VERSION 5.8 ;
BUSBITCHARS "[]" ;
DIVIDERCHAR "/" ;
UNITS
    DATABASE MICRONS 1000 ;
END UNITS

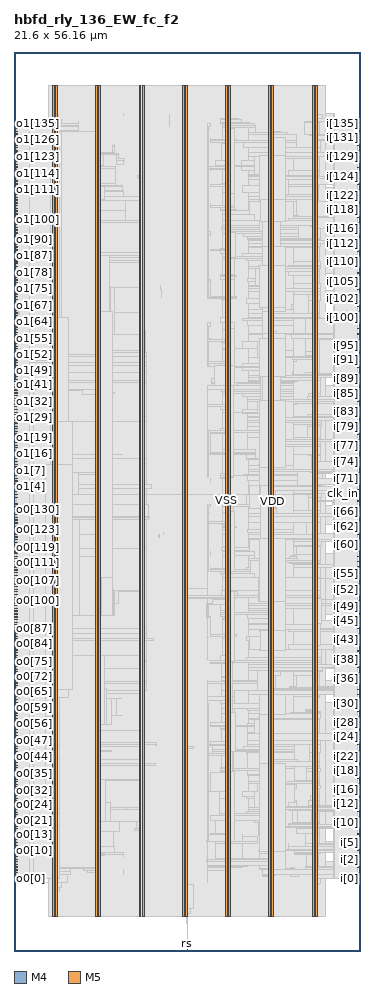
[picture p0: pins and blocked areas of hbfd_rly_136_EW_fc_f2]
MACRO hbfd_rly_136_EW_fc_f2
  FOREIGN hbfd_rly_136_EW_fc_f2 0 0 ;
  CLASS BLOCK ;
  SIZE 21.6 BY 56.16 ;
  PIN clk_in
    DIRECTION INPUT ;
    USE SIGNAL ;
    PORT
      LAYER M4 ;
        RECT  21.408 28.08 21.6 28.104 ;
    END
  END clk_in
  PIN clk_out0
    DIRECTION OUTPUT ;
    USE SIGNAL ;
    PORT
      LAYER M4 ;
        RECT  0 16.224 0.192 16.248 ;
    END
  END clk_out0
  PIN clk_out1
    DIRECTION OUTPUT ;
    USE SIGNAL ;
    PORT
      LAYER M4 ;
        RECT  0 39.984 0.192 40.008 ;
    END
  END clk_out1
  PIN i[0]
    DIRECTION INPUT ;
    USE SIGNAL ;
    PORT
      LAYER M4 ;
        RECT  21.408 4.512 21.6 4.536 ;
    END
  END i[0]
  PIN i[100]
    DIRECTION INPUT ;
    USE SIGNAL ;
    PORT
      LAYER M4 ;
        RECT  21.408 39.504 21.6 39.528 ;
    END
  END i[100]
  PIN i[101]
    DIRECTION INPUT ;
    USE SIGNAL ;
    PORT
      LAYER M4 ;
        RECT  21.408 39.888 21.6 39.912 ;
    END
  END i[101]
  PIN i[102]
    DIRECTION INPUT ;
    USE SIGNAL ;
    PORT
      LAYER M4 ;
        RECT  21.408 40.224 21.6 40.248 ;
    END
  END i[102]
  PIN i[103]
    DIRECTION INPUT ;
    USE SIGNAL ;
    PORT
      LAYER M4 ;
        RECT  21.408 40.56 21.6 40.584 ;
    END
  END i[103]
  PIN i[104]
    DIRECTION INPUT ;
    USE SIGNAL ;
    PORT
      LAYER M4 ;
        RECT  21.408 40.896 21.6 40.92 ;
    END
  END i[104]
  PIN i[105]
    DIRECTION INPUT ;
    USE SIGNAL ;
    PORT
      LAYER M4 ;
        RECT  21.408 41.28 21.6 41.304 ;
    END
  END i[105]
  PIN i[106]
    DIRECTION INPUT ;
    USE SIGNAL ;
    PORT
      LAYER M4 ;
        RECT  21.408 41.616 21.6 41.64 ;
    END
  END i[106]
  PIN i[107]
    DIRECTION INPUT ;
    USE SIGNAL ;
    PORT
      LAYER M4 ;
        RECT  21.408 41.952 21.6 41.976 ;
    END
  END i[107]
  PIN i[108]
    DIRECTION INPUT ;
    USE SIGNAL ;
    PORT
      LAYER M4 ;
        RECT  21.408 42.288 21.6 42.312 ;
    END
  END i[108]
  PIN i[109]
    DIRECTION INPUT ;
    USE SIGNAL ;
    PORT
      LAYER M4 ;
        RECT  21.408 42.624 21.6 42.648 ;
    END
  END i[109]
  PIN i[10]
    DIRECTION INPUT ;
    USE SIGNAL ;
    PORT
      LAYER M4 ;
        RECT  21.408 8.016 21.6 8.04 ;
    END
  END i[10]
  PIN i[110]
    DIRECTION INPUT ;
    USE SIGNAL ;
    PORT
      LAYER M4 ;
        RECT  21.408 43.008 21.6 43.032 ;
    END
  END i[110]
  PIN i[111]
    DIRECTION INPUT ;
    USE SIGNAL ;
    PORT
      LAYER M4 ;
        RECT  21.408 43.344 21.6 43.368 ;
    END
  END i[111]
  PIN i[112]
    DIRECTION INPUT ;
    USE SIGNAL ;
    PORT
      LAYER M4 ;
        RECT  21.408 43.68 21.6 43.704 ;
    END
  END i[112]
  PIN i[113]
    DIRECTION INPUT ;
    USE SIGNAL ;
    PORT
      LAYER M4 ;
        RECT  21.408 44.016 21.6 44.04 ;
    END
  END i[113]
  PIN i[114]
    DIRECTION INPUT ;
    USE SIGNAL ;
    PORT
      LAYER M4 ;
        RECT  21.408 44.4 21.6 44.424 ;
    END
  END i[114]
  PIN i[115]
    DIRECTION INPUT ;
    USE SIGNAL ;
    PORT
      LAYER M4 ;
        RECT  21.408 44.736 21.6 44.76 ;
    END
  END i[115]
  PIN i[116]
    DIRECTION INPUT ;
    USE SIGNAL ;
    PORT
      LAYER M4 ;
        RECT  21.408 45.072 21.6 45.096 ;
    END
  END i[116]
  PIN i[117]
    DIRECTION INPUT ;
    USE SIGNAL ;
    PORT
      LAYER M4 ;
        RECT  21.408 45.408 21.6 45.432 ;
    END
  END i[117]
  PIN i[118]
    DIRECTION INPUT ;
    USE SIGNAL ;
    PORT
      LAYER M4 ;
        RECT  21.408 45.744 21.6 45.768 ;
    END
  END i[118]
  PIN i[119]
    DIRECTION INPUT ;
    USE SIGNAL ;
    PORT
      LAYER M4 ;
        RECT  21.408 46.128 21.6 46.152 ;
    END
  END i[119]
  PIN i[11]
    DIRECTION INPUT ;
    USE SIGNAL ;
    PORT
      LAYER M4 ;
        RECT  21.408 8.352 21.6 8.376 ;
    END
  END i[11]
  PIN i[120]
    DIRECTION INPUT ;
    USE SIGNAL ;
    PORT
      LAYER M4 ;
        RECT  21.408 46.464 21.6 46.488 ;
    END
  END i[120]
  PIN i[121]
    DIRECTION INPUT ;
    USE SIGNAL ;
    PORT
      LAYER M4 ;
        RECT  21.408 46.8 21.6 46.824 ;
    END
  END i[121]
  PIN i[122]
    DIRECTION INPUT ;
    USE SIGNAL ;
    PORT
      LAYER M4 ;
        RECT  21.408 47.136 21.6 47.16 ;
    END
  END i[122]
  PIN i[123]
    DIRECTION INPUT ;
    USE SIGNAL ;
    PORT
      LAYER M4 ;
        RECT  21.408 47.472 21.6 47.496 ;
    END
  END i[123]
  PIN i[124]
    DIRECTION INPUT ;
    USE SIGNAL ;
    PORT
      LAYER M4 ;
        RECT  21.408 47.856 21.6 47.88 ;
    END
  END i[124]
  PIN i[125]
    DIRECTION INPUT ;
    USE SIGNAL ;
    PORT
      LAYER M4 ;
        RECT  21.408 48.192 21.6 48.216 ;
    END
  END i[125]
  PIN i[126]
    DIRECTION INPUT ;
    USE SIGNAL ;
    PORT
      LAYER M4 ;
        RECT  21.408 48.528 21.6 48.552 ;
    END
  END i[126]
  PIN i[127]
    DIRECTION INPUT ;
    USE SIGNAL ;
    PORT
      LAYER M4 ;
        RECT  21.408 48.864 21.6 48.888 ;
    END
  END i[127]
  PIN i[128]
    DIRECTION INPUT ;
    USE SIGNAL ;
    PORT
      LAYER M4 ;
        RECT  21.408 49.248 21.6 49.272 ;
    END
  END i[128]
  PIN i[129]
    DIRECTION INPUT ;
    USE SIGNAL ;
    PORT
      LAYER M4 ;
        RECT  21.408 49.584 21.6 49.608 ;
    END
  END i[129]
  PIN i[12]
    DIRECTION INPUT ;
    USE SIGNAL ;
    PORT
      LAYER M4 ;
        RECT  21.408 8.688 21.6 8.712 ;
    END
  END i[12]
  PIN i[130]
    DIRECTION INPUT ;
    USE SIGNAL ;
    PORT
      LAYER M4 ;
        RECT  21.408 49.92 21.6 49.944 ;
    END
  END i[130]
  PIN i[131]
    DIRECTION INPUT ;
    USE SIGNAL ;
    PORT
      LAYER M4 ;
        RECT  21.408 50.256 21.6 50.28 ;
    END
  END i[131]
  PIN i[132]
    DIRECTION INPUT ;
    USE SIGNAL ;
    PORT
      LAYER M4 ;
        RECT  21.408 50.592 21.6 50.616 ;
    END
  END i[132]
  PIN i[133]
    DIRECTION INPUT ;
    USE SIGNAL ;
    PORT
      LAYER M4 ;
        RECT  21.408 50.976 21.6 51 ;
    END
  END i[133]
  PIN i[134]
    DIRECTION INPUT ;
    USE SIGNAL ;
    PORT
      LAYER M4 ;
        RECT  21.408 51.312 21.6 51.336 ;
    END
  END i[134]
  PIN i[135]
    DIRECTION INPUT ;
    USE SIGNAL ;
    PORT
      LAYER M4 ;
        RECT  21.408 51.648 21.6 51.672 ;
    END
  END i[135]
  PIN i[13]
    DIRECTION INPUT ;
    USE SIGNAL ;
    PORT
      LAYER M4 ;
        RECT  21.408 9.024 21.6 9.048 ;
    END
  END i[13]
  PIN i[14]
    DIRECTION INPUT ;
    USE SIGNAL ;
    PORT
      LAYER M4 ;
        RECT  21.408 9.36 21.6 9.384 ;
    END
  END i[14]
  PIN i[15]
    DIRECTION INPUT ;
    USE SIGNAL ;
    PORT
      LAYER M4 ;
        RECT  21.408 9.744 21.6 9.768 ;
    END
  END i[15]
  PIN i[16]
    DIRECTION INPUT ;
    USE SIGNAL ;
    PORT
      LAYER M4 ;
        RECT  21.408 10.08 21.6 10.104 ;
    END
  END i[16]
  PIN i[17]
    DIRECTION INPUT ;
    USE SIGNAL ;
    PORT
      LAYER M4 ;
        RECT  21.408 10.416 21.6 10.44 ;
    END
  END i[17]
  PIN i[18]
    DIRECTION INPUT ;
    USE SIGNAL ;
    PORT
      LAYER M4 ;
        RECT  21.408 10.752 21.6 10.776 ;
    END
  END i[18]
  PIN i[19]
    DIRECTION INPUT ;
    USE SIGNAL ;
    PORT
      LAYER M4 ;
        RECT  21.408 11.136 21.6 11.16 ;
    END
  END i[19]
  PIN i[1]
    DIRECTION INPUT ;
    USE SIGNAL ;
    PORT
      LAYER M4 ;
        RECT  21.408 4.896 21.6 4.92 ;
    END
  END i[1]
  PIN i[20]
    DIRECTION INPUT ;
    USE SIGNAL ;
    PORT
      LAYER M4 ;
        RECT  21.408 11.472 21.6 11.496 ;
    END
  END i[20]
  PIN i[21]
    DIRECTION INPUT ;
    USE SIGNAL ;
    PORT
      LAYER M4 ;
        RECT  21.408 11.808 21.6 11.832 ;
    END
  END i[21]
  PIN i[22]
    DIRECTION INPUT ;
    USE SIGNAL ;
    PORT
      LAYER M4 ;
        RECT  21.408 12.144 21.6 12.168 ;
    END
  END i[22]
  PIN i[23]
    DIRECTION INPUT ;
    USE SIGNAL ;
    PORT
      LAYER M4 ;
        RECT  21.408 12.48 21.6 12.504 ;
    END
  END i[23]
  PIN i[24]
    DIRECTION INPUT ;
    USE SIGNAL ;
    PORT
      LAYER M4 ;
        RECT  21.408 12.864 21.6 12.888 ;
    END
  END i[24]
  PIN i[25]
    DIRECTION INPUT ;
    USE SIGNAL ;
    PORT
      LAYER M4 ;
        RECT  21.408 13.2 21.6 13.224 ;
    END
  END i[25]
  PIN i[26]
    DIRECTION INPUT ;
    USE SIGNAL ;
    PORT
      LAYER M4 ;
        RECT  21.408 13.536 21.6 13.56 ;
    END
  END i[26]
  PIN i[27]
    DIRECTION INPUT ;
    USE SIGNAL ;
    PORT
      LAYER M4 ;
        RECT  21.408 13.872 21.6 13.896 ;
    END
  END i[27]
  PIN i[28]
    DIRECTION INPUT ;
    USE SIGNAL ;
    PORT
      LAYER M4 ;
        RECT  21.408 14.256 21.6 14.28 ;
    END
  END i[28]
  PIN i[29]
    DIRECTION INPUT ;
    USE SIGNAL ;
    PORT
      LAYER M4 ;
        RECT  21.408 14.592 21.6 14.616 ;
    END
  END i[29]
  PIN i[2]
    DIRECTION INPUT ;
    USE SIGNAL ;
    PORT
      LAYER M4 ;
        RECT  21.408 5.232 21.6 5.256 ;
    END
  END i[2]
  PIN i[30]
    DIRECTION INPUT ;
    USE SIGNAL ;
    PORT
      LAYER M4 ;
        RECT  21.408 14.928 21.6 14.952 ;
    END
  END i[30]
  PIN i[31]
    DIRECTION INPUT ;
    USE SIGNAL ;
    PORT
      LAYER M4 ;
        RECT  21.408 15.264 21.6 15.288 ;
    END
  END i[31]
  PIN i[32]
    DIRECTION INPUT ;
    USE SIGNAL ;
    PORT
      LAYER M4 ;
        RECT  21.408 15.6 21.6 15.624 ;
    END
  END i[32]
  PIN i[33]
    DIRECTION INPUT ;
    USE SIGNAL ;
    PORT
      LAYER M4 ;
        RECT  21.408 15.984 21.6 16.008 ;
    END
  END i[33]
  PIN i[34]
    DIRECTION INPUT ;
    USE SIGNAL ;
    PORT
      LAYER M4 ;
        RECT  21.408 16.32 21.6 16.344 ;
    END
  END i[34]
  PIN i[35]
    DIRECTION INPUT ;
    USE SIGNAL ;
    PORT
      LAYER M4 ;
        RECT  21.408 16.656 21.6 16.68 ;
    END
  END i[35]
  PIN i[36]
    DIRECTION INPUT ;
    USE SIGNAL ;
    PORT
      LAYER M4 ;
        RECT  21.408 16.992 21.6 17.016 ;
    END
  END i[36]
  PIN i[37]
    DIRECTION INPUT ;
    USE SIGNAL ;
    PORT
      LAYER M4 ;
        RECT  21.408 17.328 21.6 17.352 ;
    END
  END i[37]
  PIN i[38]
    DIRECTION INPUT ;
    USE SIGNAL ;
    PORT
      LAYER M4 ;
        RECT  21.408 17.712 21.6 17.736 ;
    END
  END i[38]
  PIN i[39]
    DIRECTION INPUT ;
    USE SIGNAL ;
    PORT
      LAYER M4 ;
        RECT  21.408 18.048 21.6 18.072 ;
    END
  END i[39]
  PIN i[3]
    DIRECTION INPUT ;
    USE SIGNAL ;
    PORT
      LAYER M4 ;
        RECT  21.408 5.568 21.6 5.592 ;
    END
  END i[3]
  PIN i[40]
    DIRECTION INPUT ;
    USE SIGNAL ;
    PORT
      LAYER M4 ;
        RECT  21.408 18.384 21.6 18.408 ;
    END
  END i[40]
  PIN i[41]
    DIRECTION INPUT ;
    USE SIGNAL ;
    PORT
      LAYER M4 ;
        RECT  21.408 18.72 21.6 18.744 ;
    END
  END i[41]
  PIN i[42]
    DIRECTION INPUT ;
    USE SIGNAL ;
    PORT
      LAYER M4 ;
        RECT  21.408 19.104 21.6 19.128 ;
    END
  END i[42]
  PIN i[43]
    DIRECTION INPUT ;
    USE SIGNAL ;
    PORT
      LAYER M4 ;
        RECT  21.408 19.44 21.6 19.464 ;
    END
  END i[43]
  PIN i[44]
    DIRECTION INPUT ;
    USE SIGNAL ;
    PORT
      LAYER M4 ;
        RECT  21.408 19.776 21.6 19.8 ;
    END
  END i[44]
  PIN i[45]
    DIRECTION INPUT ;
    USE SIGNAL ;
    PORT
      LAYER M4 ;
        RECT  21.408 20.112 21.6 20.136 ;
    END
  END i[45]
  PIN i[46]
    DIRECTION INPUT ;
    USE SIGNAL ;
    PORT
      LAYER M4 ;
        RECT  21.408 20.448 21.6 20.472 ;
    END
  END i[46]
  PIN i[47]
    DIRECTION INPUT ;
    USE SIGNAL ;
    PORT
      LAYER M4 ;
        RECT  21.408 20.832 21.6 20.856 ;
    END
  END i[47]
  PIN i[48]
    DIRECTION INPUT ;
    USE SIGNAL ;
    PORT
      LAYER M4 ;
        RECT  21.408 21.168 21.6 21.192 ;
    END
  END i[48]
  PIN i[49]
    DIRECTION INPUT ;
    USE SIGNAL ;
    PORT
      LAYER M4 ;
        RECT  21.408 21.504 21.6 21.528 ;
    END
  END i[49]
  PIN i[4]
    DIRECTION INPUT ;
    USE SIGNAL ;
    PORT
      LAYER M4 ;
        RECT  21.408 5.904 21.6 5.928 ;
    END
  END i[4]
  PIN i[50]
    DIRECTION INPUT ;
    USE SIGNAL ;
    PORT
      LAYER M4 ;
        RECT  21.408 21.84 21.6 21.864 ;
    END
  END i[50]
  PIN i[51]
    DIRECTION INPUT ;
    USE SIGNAL ;
    PORT
      LAYER M4 ;
        RECT  21.408 22.224 21.6 22.248 ;
    END
  END i[51]
  PIN i[52]
    DIRECTION INPUT ;
    USE SIGNAL ;
    PORT
      LAYER M4 ;
        RECT  21.408 22.56 21.6 22.584 ;
    END
  END i[52]
  PIN i[53]
    DIRECTION INPUT ;
    USE SIGNAL ;
    PORT
      LAYER M4 ;
        RECT  21.408 22.896 21.6 22.92 ;
    END
  END i[53]
  PIN i[54]
    DIRECTION INPUT ;
    USE SIGNAL ;
    PORT
      LAYER M4 ;
        RECT  21.408 23.232 21.6 23.256 ;
    END
  END i[54]
  PIN i[55]
    DIRECTION INPUT ;
    USE SIGNAL ;
    PORT
      LAYER M4 ;
        RECT  21.408 23.568 21.6 23.592 ;
    END
  END i[55]
  PIN i[56]
    DIRECTION INPUT ;
    USE SIGNAL ;
    PORT
      LAYER M4 ;
        RECT  21.408 23.952 21.6 23.976 ;
    END
  END i[56]
  PIN i[57]
    DIRECTION INPUT ;
    USE SIGNAL ;
    PORT
      LAYER M4 ;
        RECT  21.408 24.288 21.6 24.312 ;
    END
  END i[57]
  PIN i[58]
    DIRECTION INPUT ;
    USE SIGNAL ;
    PORT
      LAYER M4 ;
        RECT  21.408 24.624 21.6 24.648 ;
    END
  END i[58]
  PIN i[59]
    DIRECTION INPUT ;
    USE SIGNAL ;
    PORT
      LAYER M4 ;
        RECT  21.408 24.96 21.6 24.984 ;
    END
  END i[59]
  PIN i[5]
    DIRECTION INPUT ;
    USE SIGNAL ;
    PORT
      LAYER M4 ;
        RECT  21.408 6.288 21.6 6.312 ;
    END
  END i[5]
  PIN i[60]
    DIRECTION INPUT ;
    USE SIGNAL ;
    PORT
      LAYER M4 ;
        RECT  21.408 25.344 21.6 25.368 ;
    END
  END i[60]
  PIN i[61]
    DIRECTION INPUT ;
    USE SIGNAL ;
    PORT
      LAYER M4 ;
        RECT  21.408 25.68 21.6 25.704 ;
    END
  END i[61]
  PIN i[62]
    DIRECTION INPUT ;
    USE SIGNAL ;
    PORT
      LAYER M4 ;
        RECT  21.408 26.016 21.6 26.04 ;
    END
  END i[62]
  PIN i[63]
    DIRECTION INPUT ;
    USE SIGNAL ;
    PORT
      LAYER M4 ;
        RECT  21.408 26.352 21.6 26.376 ;
    END
  END i[63]
  PIN i[64]
    DIRECTION INPUT ;
    USE SIGNAL ;
    PORT
      LAYER M4 ;
        RECT  21.408 26.688 21.6 26.712 ;
    END
  END i[64]
  PIN i[65]
    DIRECTION INPUT ;
    USE SIGNAL ;
    PORT
      LAYER M4 ;
        RECT  21.408 27.072 21.6 27.096 ;
    END
  END i[65]
  PIN i[66]
    DIRECTION INPUT ;
    USE SIGNAL ;
    PORT
      LAYER M4 ;
        RECT  21.408 27.408 21.6 27.432 ;
    END
  END i[66]
  PIN i[67]
    DIRECTION INPUT ;
    USE SIGNAL ;
    PORT
      LAYER M4 ;
        RECT  21.408 27.744 21.6 27.768 ;
    END
  END i[67]
  PIN i[68]
    DIRECTION INPUT ;
    USE SIGNAL ;
    PORT
      LAYER M4 ;
        RECT  21.408 28.416 21.6 28.44 ;
    END
  END i[68]
  PIN i[69]
    DIRECTION INPUT ;
    USE SIGNAL ;
    PORT
      LAYER M4 ;
        RECT  21.408 28.8 21.6 28.824 ;
    END
  END i[69]
  PIN i[6]
    DIRECTION INPUT ;
    USE SIGNAL ;
    PORT
      LAYER M4 ;
        RECT  21.408 6.624 21.6 6.648 ;
    END
  END i[6]
  PIN i[70]
    DIRECTION INPUT ;
    USE SIGNAL ;
    PORT
      LAYER M4 ;
        RECT  21.408 29.136 21.6 29.16 ;
    END
  END i[70]
  PIN i[71]
    DIRECTION INPUT ;
    USE SIGNAL ;
    PORT
      LAYER M4 ;
        RECT  21.408 29.472 21.6 29.496 ;
    END
  END i[71]
  PIN i[72]
    DIRECTION INPUT ;
    USE SIGNAL ;
    PORT
      LAYER M4 ;
        RECT  21.408 29.808 21.6 29.832 ;
    END
  END i[72]
  PIN i[73]
    DIRECTION INPUT ;
    USE SIGNAL ;
    PORT
      LAYER M4 ;
        RECT  21.408 30.192 21.6 30.216 ;
    END
  END i[73]
  PIN i[74]
    DIRECTION INPUT ;
    USE SIGNAL ;
    PORT
      LAYER M4 ;
        RECT  21.408 30.528 21.6 30.552 ;
    END
  END i[74]
  PIN i[75]
    DIRECTION INPUT ;
    USE SIGNAL ;
    PORT
      LAYER M4 ;
        RECT  21.408 30.864 21.6 30.888 ;
    END
  END i[75]
  PIN i[76]
    DIRECTION INPUT ;
    USE SIGNAL ;
    PORT
      LAYER M4 ;
        RECT  21.408 31.2 21.6 31.224 ;
    END
  END i[76]
  PIN i[77]
    DIRECTION INPUT ;
    USE SIGNAL ;
    PORT
      LAYER M4 ;
        RECT  21.408 31.536 21.6 31.56 ;
    END
  END i[77]
  PIN i[78]
    DIRECTION INPUT ;
    USE SIGNAL ;
    PORT
      LAYER M4 ;
        RECT  21.408 31.92 21.6 31.944 ;
    END
  END i[78]
  PIN i[79]
    DIRECTION INPUT ;
    USE SIGNAL ;
    PORT
      LAYER M4 ;
        RECT  21.408 32.256 21.6 32.28 ;
    END
  END i[79]
  PIN i[7]
    DIRECTION INPUT ;
    USE SIGNAL ;
    PORT
      LAYER M4 ;
        RECT  21.408 6.96 21.6 6.984 ;
    END
  END i[7]
  PIN i[80]
    DIRECTION INPUT ;
    USE SIGNAL ;
    PORT
      LAYER M4 ;
        RECT  21.408 32.592 21.6 32.616 ;
    END
  END i[80]
  PIN i[81]
    DIRECTION INPUT ;
    USE SIGNAL ;
    PORT
      LAYER M4 ;
        RECT  21.408 32.928 21.6 32.952 ;
    END
  END i[81]
  PIN i[82]
    DIRECTION INPUT ;
    USE SIGNAL ;
    PORT
      LAYER M4 ;
        RECT  21.408 33.312 21.6 33.336 ;
    END
  END i[82]
  PIN i[83]
    DIRECTION INPUT ;
    USE SIGNAL ;
    PORT
      LAYER M4 ;
        RECT  21.408 33.648 21.6 33.672 ;
    END
  END i[83]
  PIN i[84]
    DIRECTION INPUT ;
    USE SIGNAL ;
    PORT
      LAYER M4 ;
        RECT  21.408 33.984 21.6 34.008 ;
    END
  END i[84]
  PIN i[85]
    DIRECTION INPUT ;
    USE SIGNAL ;
    PORT
      LAYER M4 ;
        RECT  21.408 34.32 21.6 34.344 ;
    END
  END i[85]
  PIN i[86]
    DIRECTION INPUT ;
    USE SIGNAL ;
    PORT
      LAYER M4 ;
        RECT  21.408 34.656 21.6 34.68 ;
    END
  END i[86]
  PIN i[87]
    DIRECTION INPUT ;
    USE SIGNAL ;
    PORT
      LAYER M4 ;
        RECT  21.408 35.04 21.6 35.064 ;
    END
  END i[87]
  PIN i[88]
    DIRECTION INPUT ;
    USE SIGNAL ;
    PORT
      LAYER M4 ;
        RECT  21.408 35.376 21.6 35.4 ;
    END
  END i[88]
  PIN i[89]
    DIRECTION INPUT ;
    USE SIGNAL ;
    PORT
      LAYER M4 ;
        RECT  21.408 35.712 21.6 35.736 ;
    END
  END i[89]
  PIN i[8]
    DIRECTION INPUT ;
    USE SIGNAL ;
    PORT
      LAYER M4 ;
        RECT  21.408 7.296 21.6 7.32 ;
    END
  END i[8]
  PIN i[90]
    DIRECTION INPUT ;
    USE SIGNAL ;
    PORT
      LAYER M4 ;
        RECT  21.408 36.048 21.6 36.072 ;
    END
  END i[90]
  PIN i[91]
    DIRECTION INPUT ;
    USE SIGNAL ;
    PORT
      LAYER M4 ;
        RECT  21.408 36.384 21.6 36.408 ;
    END
  END i[91]
  PIN i[92]
    DIRECTION INPUT ;
    USE SIGNAL ;
    PORT
      LAYER M4 ;
        RECT  21.408 36.768 21.6 36.792 ;
    END
  END i[92]
  PIN i[93]
    DIRECTION INPUT ;
    USE SIGNAL ;
    PORT
      LAYER M4 ;
        RECT  21.408 37.104 21.6 37.128 ;
    END
  END i[93]
  PIN i[94]
    DIRECTION INPUT ;
    USE SIGNAL ;
    PORT
      LAYER M4 ;
        RECT  21.408 37.44 21.6 37.464 ;
    END
  END i[94]
  PIN i[95]
    DIRECTION INPUT ;
    USE SIGNAL ;
    PORT
      LAYER M4 ;
        RECT  21.408 37.776 21.6 37.8 ;
    END
  END i[95]
  PIN i[96]
    DIRECTION INPUT ;
    USE SIGNAL ;
    PORT
      LAYER M4 ;
        RECT  21.408 38.16 21.6 38.184 ;
    END
  END i[96]
  PIN i[97]
    DIRECTION INPUT ;
    USE SIGNAL ;
    PORT
      LAYER M4 ;
        RECT  21.408 38.496 21.6 38.52 ;
    END
  END i[97]
  PIN i[98]
    DIRECTION INPUT ;
    USE SIGNAL ;
    PORT
      LAYER M4 ;
        RECT  21.408 38.832 21.6 38.856 ;
    END
  END i[98]
  PIN i[99]
    DIRECTION INPUT ;
    USE SIGNAL ;
    PORT
      LAYER M4 ;
        RECT  21.408 39.168 21.6 39.192 ;
    END
  END i[99]
  PIN i[9]
    DIRECTION INPUT ;
    USE SIGNAL ;
    PORT
      LAYER M4 ;
        RECT  21.408 7.632 21.6 7.656 ;
    END
  END i[9]
  PIN o0[0]
    DIRECTION OUTPUT ;
    USE SIGNAL ;
    PORT
      LAYER M4 ;
        RECT  0 4.512 0.192 4.536 ;
    END
  END o0[0]
  PIN o0[100]
    DIRECTION OUTPUT ;
    USE SIGNAL ;
    PORT
      LAYER M4 ;
        RECT  0 21.888 0.192 21.912 ;
    END
  END o0[100]
  PIN o0[101]
    DIRECTION OUTPUT ;
    USE SIGNAL ;
    PORT
      LAYER M4 ;
        RECT  0 22.032 0.192 22.056 ;
    END
  END o0[101]
  PIN o0[102]
    DIRECTION OUTPUT ;
    USE SIGNAL ;
    PORT
      LAYER M4 ;
        RECT  0 22.224 0.192 22.248 ;
    END
  END o0[102]
  PIN o0[103]
    DIRECTION OUTPUT ;
    USE SIGNAL ;
    PORT
      LAYER M4 ;
        RECT  0 22.416 0.192 22.44 ;
    END
  END o0[103]
  PIN o0[104]
    DIRECTION OUTPUT ;
    USE SIGNAL ;
    PORT
      LAYER M4 ;
        RECT  0 22.56 0.192 22.584 ;
    END
  END o0[104]
  PIN o0[105]
    DIRECTION OUTPUT ;
    USE SIGNAL ;
    PORT
      LAYER M4 ;
        RECT  0 22.752 0.192 22.776 ;
    END
  END o0[105]
  PIN o0[106]
    DIRECTION OUTPUT ;
    USE SIGNAL ;
    PORT
      LAYER M4 ;
        RECT  0 22.896 0.192 22.92 ;
    END
  END o0[106]
  PIN o0[107]
    DIRECTION OUTPUT ;
    USE SIGNAL ;
    PORT
      LAYER M4 ;
        RECT  0 23.088 0.192 23.112 ;
    END
  END o0[107]
  PIN o0[108]
    DIRECTION OUTPUT ;
    USE SIGNAL ;
    PORT
      LAYER M4 ;
        RECT  0 23.232 0.192 23.256 ;
    END
  END o0[108]
  PIN o0[109]
    DIRECTION OUTPUT ;
    USE SIGNAL ;
    PORT
      LAYER M4 ;
        RECT  0 23.424 0.192 23.448 ;
    END
  END o0[109]
  PIN o0[10]
    DIRECTION OUTPUT ;
    USE SIGNAL ;
    PORT
      LAYER M4 ;
        RECT  0 6.24 0.192 6.264 ;
    END
  END o0[10]
  PIN o0[110]
    DIRECTION OUTPUT ;
    USE SIGNAL ;
    PORT
      LAYER M4 ;
        RECT  0 23.616 0.192 23.64 ;
    END
  END o0[110]
  PIN o0[111]
    DIRECTION OUTPUT ;
    USE SIGNAL ;
    PORT
      LAYER M4 ;
        RECT  0 23.76 0.192 23.784 ;
    END
  END o0[111]
  PIN o0[112]
    DIRECTION OUTPUT ;
    USE SIGNAL ;
    PORT
      LAYER M4 ;
        RECT  0 23.952 0.192 23.976 ;
    END
  END o0[112]
  PIN o0[113]
    DIRECTION OUTPUT ;
    USE SIGNAL ;
    PORT
      LAYER M4 ;
        RECT  0 24.096 0.192 24.12 ;
    END
  END o0[113]
  PIN o0[114]
    DIRECTION OUTPUT ;
    USE SIGNAL ;
    PORT
      LAYER M4 ;
        RECT  0 24.288 0.192 24.312 ;
    END
  END o0[114]
  PIN o0[115]
    DIRECTION OUTPUT ;
    USE SIGNAL ;
    PORT
      LAYER M4 ;
        RECT  0 24.48 0.192 24.504 ;
    END
  END o0[115]
  PIN o0[116]
    DIRECTION OUTPUT ;
    USE SIGNAL ;
    PORT
      LAYER M4 ;
        RECT  0 24.624 0.192 24.648 ;
    END
  END o0[116]
  PIN o0[117]
    DIRECTION OUTPUT ;
    USE SIGNAL ;
    PORT
      LAYER M4 ;
        RECT  0 24.816 0.192 24.84 ;
    END
  END o0[117]
  PIN o0[118]
    DIRECTION OUTPUT ;
    USE SIGNAL ;
    PORT
      LAYER M4 ;
        RECT  0 24.96 0.192 24.984 ;
    END
  END o0[118]
  PIN o0[119]
    DIRECTION OUTPUT ;
    USE SIGNAL ;
    PORT
      LAYER M4 ;
        RECT  0 25.152 0.192 25.176 ;
    END
  END o0[119]
  PIN o0[11]
    DIRECTION OUTPUT ;
    USE SIGNAL ;
    PORT
      LAYER M4 ;
        RECT  0 6.432 0.192 6.456 ;
    END
  END o0[11]
  PIN o0[120]
    DIRECTION OUTPUT ;
    USE SIGNAL ;
    PORT
      LAYER M4 ;
        RECT  0 25.296 0.192 25.32 ;
    END
  END o0[120]
  PIN o0[121]
    DIRECTION OUTPUT ;
    USE SIGNAL ;
    PORT
      LAYER M4 ;
        RECT  0 25.488 0.192 25.512 ;
    END
  END o0[121]
  PIN o0[122]
    DIRECTION OUTPUT ;
    USE SIGNAL ;
    PORT
      LAYER M4 ;
        RECT  0 25.68 0.192 25.704 ;
    END
  END o0[122]
  PIN o0[123]
    DIRECTION OUTPUT ;
    USE SIGNAL ;
    PORT
      LAYER M4 ;
        RECT  0 25.824 0.192 25.848 ;
    END
  END o0[123]
  PIN o0[124]
    DIRECTION OUTPUT ;
    USE SIGNAL ;
    PORT
      LAYER M4 ;
        RECT  0 26.016 0.192 26.04 ;
    END
  END o0[124]
  PIN o0[125]
    DIRECTION OUTPUT ;
    USE SIGNAL ;
    PORT
      LAYER M4 ;
        RECT  0 26.16 0.192 26.184 ;
    END
  END o0[125]
  PIN o0[126]
    DIRECTION OUTPUT ;
    USE SIGNAL ;
    PORT
      LAYER M4 ;
        RECT  0 26.352 0.192 26.376 ;
    END
  END o0[126]
  PIN o0[127]
    DIRECTION OUTPUT ;
    USE SIGNAL ;
    PORT
      LAYER M4 ;
        RECT  0 26.496 0.192 26.52 ;
    END
  END o0[127]
  PIN o0[128]
    DIRECTION OUTPUT ;
    USE SIGNAL ;
    PORT
      LAYER M4 ;
        RECT  0 26.688 0.192 26.712 ;
    END
  END o0[128]
  PIN o0[129]
    DIRECTION OUTPUT ;
    USE SIGNAL ;
    PORT
      LAYER M4 ;
        RECT  0 26.88 0.192 26.904 ;
    END
  END o0[129]
  PIN o0[12]
    DIRECTION OUTPUT ;
    USE SIGNAL ;
    PORT
      LAYER M4 ;
        RECT  0 6.576 0.192 6.6 ;
    END
  END o0[12]
  PIN o0[130]
    DIRECTION OUTPUT ;
    USE SIGNAL ;
    PORT
      LAYER M4 ;
        RECT  0 27.024 0.192 27.048 ;
    END
  END o0[130]
  PIN o0[131]
    DIRECTION OUTPUT ;
    USE SIGNAL ;
    PORT
      LAYER M4 ;
        RECT  0 27.216 0.192 27.24 ;
    END
  END o0[131]
  PIN o0[132]
    DIRECTION OUTPUT ;
    USE SIGNAL ;
    PORT
      LAYER M4 ;
        RECT  0 27.36 0.192 27.384 ;
    END
  END o0[132]
  PIN o0[133]
    DIRECTION OUTPUT ;
    USE SIGNAL ;
    PORT
      LAYER M4 ;
        RECT  0 27.552 0.192 27.576 ;
    END
  END o0[133]
  PIN o0[134]
    DIRECTION OUTPUT ;
    USE SIGNAL ;
    PORT
      LAYER M4 ;
        RECT  0 27.744 0.192 27.768 ;
    END
  END o0[134]
  PIN o0[135]
    DIRECTION OUTPUT ;
    USE SIGNAL ;
    PORT
      LAYER M4 ;
        RECT  0 27.888 0.192 27.912 ;
    END
  END o0[135]
  PIN o0[13]
    DIRECTION OUTPUT ;
    USE SIGNAL ;
    PORT
      LAYER M4 ;
        RECT  0 6.768 0.192 6.792 ;
    END
  END o0[13]
  PIN o0[14]
    DIRECTION OUTPUT ;
    USE SIGNAL ;
    PORT
      LAYER M4 ;
        RECT  0 6.96 0.192 6.984 ;
    END
  END o0[14]
  PIN o0[15]
    DIRECTION OUTPUT ;
    USE SIGNAL ;
    PORT
      LAYER M4 ;
        RECT  0 7.104 0.192 7.128 ;
    END
  END o0[15]
  PIN o0[16]
    DIRECTION OUTPUT ;
    USE SIGNAL ;
    PORT
      LAYER M4 ;
        RECT  0 7.296 0.192 7.32 ;
    END
  END o0[16]
  PIN o0[17]
    DIRECTION OUTPUT ;
    USE SIGNAL ;
    PORT
      LAYER M4 ;
        RECT  0 7.44 0.192 7.464 ;
    END
  END o0[17]
  PIN o0[18]
    DIRECTION OUTPUT ;
    USE SIGNAL ;
    PORT
      LAYER M4 ;
        RECT  0 7.632 0.192 7.656 ;
    END
  END o0[18]
  PIN o0[19]
    DIRECTION OUTPUT ;
    USE SIGNAL ;
    PORT
      LAYER M4 ;
        RECT  0 7.776 0.192 7.8 ;
    END
  END o0[19]
  PIN o0[1]
    DIRECTION OUTPUT ;
    USE SIGNAL ;
    PORT
      LAYER M4 ;
        RECT  0 4.704 0.192 4.728 ;
    END
  END o0[1]
  PIN o0[20]
    DIRECTION OUTPUT ;
    USE SIGNAL ;
    PORT
      LAYER M4 ;
        RECT  0 7.968 0.192 7.992 ;
    END
  END o0[20]
  PIN o0[21]
    DIRECTION OUTPUT ;
    USE SIGNAL ;
    PORT
      LAYER M4 ;
        RECT  0 8.16 0.192 8.184 ;
    END
  END o0[21]
  PIN o0[22]
    DIRECTION OUTPUT ;
    USE SIGNAL ;
    PORT
      LAYER M4 ;
        RECT  0 8.304 0.192 8.328 ;
    END
  END o0[22]
  PIN o0[23]
    DIRECTION OUTPUT ;
    USE SIGNAL ;
    PORT
      LAYER M4 ;
        RECT  0 8.496 0.192 8.52 ;
    END
  END o0[23]
  PIN o0[24]
    DIRECTION OUTPUT ;
    USE SIGNAL ;
    PORT
      LAYER M4 ;
        RECT  0 8.64 0.192 8.664 ;
    END
  END o0[24]
  PIN o0[25]
    DIRECTION OUTPUT ;
    USE SIGNAL ;
    PORT
      LAYER M4 ;
        RECT  0 8.832 0.192 8.856 ;
    END
  END o0[25]
  PIN o0[26]
    DIRECTION OUTPUT ;
    USE SIGNAL ;
    PORT
      LAYER M4 ;
        RECT  0 8.976 0.192 9 ;
    END
  END o0[26]
  PIN o0[27]
    DIRECTION OUTPUT ;
    USE SIGNAL ;
    PORT
      LAYER M4 ;
        RECT  0 9.168 0.192 9.192 ;
    END
  END o0[27]
  PIN o0[28]
    DIRECTION OUTPUT ;
    USE SIGNAL ;
    PORT
      LAYER M4 ;
        RECT  0 9.36 0.192 9.384 ;
    END
  END o0[28]
  PIN o0[29]
    DIRECTION OUTPUT ;
    USE SIGNAL ;
    PORT
      LAYER M4 ;
        RECT  0 9.504 0.192 9.528 ;
    END
  END o0[29]
  PIN o0[2]
    DIRECTION OUTPUT ;
    USE SIGNAL ;
    PORT
      LAYER M4 ;
        RECT  0 4.896 0.192 4.92 ;
    END
  END o0[2]
  PIN o0[30]
    DIRECTION OUTPUT ;
    USE SIGNAL ;
    PORT
      LAYER M4 ;
        RECT  0 9.696 0.192 9.72 ;
    END
  END o0[30]
  PIN o0[31]
    DIRECTION OUTPUT ;
    USE SIGNAL ;
    PORT
      LAYER M4 ;
        RECT  0 9.84 0.192 9.864 ;
    END
  END o0[31]
  PIN o0[32]
    DIRECTION OUTPUT ;
    USE SIGNAL ;
    PORT
      LAYER M4 ;
        RECT  0 10.032 0.192 10.056 ;
    END
  END o0[32]
  PIN o0[33]
    DIRECTION OUTPUT ;
    USE SIGNAL ;
    PORT
      LAYER M4 ;
        RECT  0 10.224 0.192 10.248 ;
    END
  END o0[33]
  PIN o0[34]
    DIRECTION OUTPUT ;
    USE SIGNAL ;
    PORT
      LAYER M4 ;
        RECT  0 10.368 0.192 10.392 ;
    END
  END o0[34]
  PIN o0[35]
    DIRECTION OUTPUT ;
    USE SIGNAL ;
    PORT
      LAYER M4 ;
        RECT  0 10.56 0.192 10.584 ;
    END
  END o0[35]
  PIN o0[36]
    DIRECTION OUTPUT ;
    USE SIGNAL ;
    PORT
      LAYER M4 ;
        RECT  0 10.704 0.192 10.728 ;
    END
  END o0[36]
  PIN o0[37]
    DIRECTION OUTPUT ;
    USE SIGNAL ;
    PORT
      LAYER M4 ;
        RECT  0 10.896 0.192 10.92 ;
    END
  END o0[37]
  PIN o0[38]
    DIRECTION OUTPUT ;
    USE SIGNAL ;
    PORT
      LAYER M4 ;
        RECT  0 11.04 0.192 11.064 ;
    END
  END o0[38]
  PIN o0[39]
    DIRECTION OUTPUT ;
    USE SIGNAL ;
    PORT
      LAYER M4 ;
        RECT  0 11.232 0.192 11.256 ;
    END
  END o0[39]
  PIN o0[3]
    DIRECTION OUTPUT ;
    USE SIGNAL ;
    PORT
      LAYER M4 ;
        RECT  0 5.04 0.192 5.064 ;
    END
  END o0[3]
  PIN o0[40]
    DIRECTION OUTPUT ;
    USE SIGNAL ;
    PORT
      LAYER M4 ;
        RECT  0 11.424 0.192 11.448 ;
    END
  END o0[40]
  PIN o0[41]
    DIRECTION OUTPUT ;
    USE SIGNAL ;
    PORT
      LAYER M4 ;
        RECT  0 11.568 0.192 11.592 ;
    END
  END o0[41]
  PIN o0[42]
    DIRECTION OUTPUT ;
    USE SIGNAL ;
    PORT
      LAYER M4 ;
        RECT  0 11.76 0.192 11.784 ;
    END
  END o0[42]
  PIN o0[43]
    DIRECTION OUTPUT ;
    USE SIGNAL ;
    PORT
      LAYER M4 ;
        RECT  0 11.904 0.192 11.928 ;
    END
  END o0[43]
  PIN o0[44]
    DIRECTION OUTPUT ;
    USE SIGNAL ;
    PORT
      LAYER M4 ;
        RECT  0 12.096 0.192 12.12 ;
    END
  END o0[44]
  PIN o0[45]
    DIRECTION OUTPUT ;
    USE SIGNAL ;
    PORT
      LAYER M4 ;
        RECT  0 12.24 0.192 12.264 ;
    END
  END o0[45]
  PIN o0[46]
    DIRECTION OUTPUT ;
    USE SIGNAL ;
    PORT
      LAYER M4 ;
        RECT  0 12.432 0.192 12.456 ;
    END
  END o0[46]
  PIN o0[47]
    DIRECTION OUTPUT ;
    USE SIGNAL ;
    PORT
      LAYER M4 ;
        RECT  0 12.624 0.192 12.648 ;
    END
  END o0[47]
  PIN o0[48]
    DIRECTION OUTPUT ;
    USE SIGNAL ;
    PORT
      LAYER M4 ;
        RECT  0 12.768 0.192 12.792 ;
    END
  END o0[48]
  PIN o0[49]
    DIRECTION OUTPUT ;
    USE SIGNAL ;
    PORT
      LAYER M4 ;
        RECT  0 12.96 0.192 12.984 ;
    END
  END o0[49]
  PIN o0[4]
    DIRECTION OUTPUT ;
    USE SIGNAL ;
    PORT
      LAYER M4 ;
        RECT  0 5.232 0.192 5.256 ;
    END
  END o0[4]
  PIN o0[50]
    DIRECTION OUTPUT ;
    USE SIGNAL ;
    PORT
      LAYER M4 ;
        RECT  0 13.104 0.192 13.128 ;
    END
  END o0[50]
  PIN o0[51]
    DIRECTION OUTPUT ;
    USE SIGNAL ;
    PORT
      LAYER M4 ;
        RECT  0 13.296 0.192 13.32 ;
    END
  END o0[51]
  PIN o0[52]
    DIRECTION OUTPUT ;
    USE SIGNAL ;
    PORT
      LAYER M4 ;
        RECT  0 13.44 0.192 13.464 ;
    END
  END o0[52]
  PIN o0[53]
    DIRECTION OUTPUT ;
    USE SIGNAL ;
    PORT
      LAYER M4 ;
        RECT  0 13.632 0.192 13.656 ;
    END
  END o0[53]
  PIN o0[54]
    DIRECTION OUTPUT ;
    USE SIGNAL ;
    PORT
      LAYER M4 ;
        RECT  0 13.824 0.192 13.848 ;
    END
  END o0[54]
  PIN o0[55]
    DIRECTION OUTPUT ;
    USE SIGNAL ;
    PORT
      LAYER M4 ;
        RECT  0 13.968 0.192 13.992 ;
    END
  END o0[55]
  PIN o0[56]
    DIRECTION OUTPUT ;
    USE SIGNAL ;
    PORT
      LAYER M4 ;
        RECT  0 14.16 0.192 14.184 ;
    END
  END o0[56]
  PIN o0[57]
    DIRECTION OUTPUT ;
    USE SIGNAL ;
    PORT
      LAYER M4 ;
        RECT  0 14.304 0.192 14.328 ;
    END
  END o0[57]
  PIN o0[58]
    DIRECTION OUTPUT ;
    USE SIGNAL ;
    PORT
      LAYER M4 ;
        RECT  0 14.496 0.192 14.52 ;
    END
  END o0[58]
  PIN o0[59]
    DIRECTION OUTPUT ;
    USE SIGNAL ;
    PORT
      LAYER M4 ;
        RECT  0 14.688 0.192 14.712 ;
    END
  END o0[59]
  PIN o0[5]
    DIRECTION OUTPUT ;
    USE SIGNAL ;
    PORT
      LAYER M4 ;
        RECT  0 5.376 0.192 5.4 ;
    END
  END o0[5]
  PIN o0[60]
    DIRECTION OUTPUT ;
    USE SIGNAL ;
    PORT
      LAYER M4 ;
        RECT  0 14.832 0.192 14.856 ;
    END
  END o0[60]
  PIN o0[61]
    DIRECTION OUTPUT ;
    USE SIGNAL ;
    PORT
      LAYER M4 ;
        RECT  0 15.024 0.192 15.048 ;
    END
  END o0[61]
  PIN o0[62]
    DIRECTION OUTPUT ;
    USE SIGNAL ;
    PORT
      LAYER M4 ;
        RECT  0 15.168 0.192 15.192 ;
    END
  END o0[62]
  PIN o0[63]
    DIRECTION OUTPUT ;
    USE SIGNAL ;
    PORT
      LAYER M4 ;
        RECT  0 15.36 0.192 15.384 ;
    END
  END o0[63]
  PIN o0[64]
    DIRECTION OUTPUT ;
    USE SIGNAL ;
    PORT
      LAYER M4 ;
        RECT  0 15.504 0.192 15.528 ;
    END
  END o0[64]
  PIN o0[65]
    DIRECTION OUTPUT ;
    USE SIGNAL ;
    PORT
      LAYER M4 ;
        RECT  0 15.696 0.192 15.72 ;
    END
  END o0[65]
  PIN o0[66]
    DIRECTION OUTPUT ;
    USE SIGNAL ;
    PORT
      LAYER M4 ;
        RECT  0 15.888 0.192 15.912 ;
    END
  END o0[66]
  PIN o0[67]
    DIRECTION OUTPUT ;
    USE SIGNAL ;
    PORT
      LAYER M4 ;
        RECT  0 16.032 0.192 16.056 ;
    END
  END o0[67]
  PIN o0[68]
    DIRECTION OUTPUT ;
    USE SIGNAL ;
    PORT
      LAYER M4 ;
        RECT  0 16.368 0.192 16.392 ;
    END
  END o0[68]
  PIN o0[69]
    DIRECTION OUTPUT ;
    USE SIGNAL ;
    PORT
      LAYER M4 ;
        RECT  0 16.56 0.192 16.584 ;
    END
  END o0[69]
  PIN o0[6]
    DIRECTION OUTPUT ;
    USE SIGNAL ;
    PORT
      LAYER M4 ;
        RECT  0 5.568 0.192 5.592 ;
    END
  END o0[6]
  PIN o0[70]
    DIRECTION OUTPUT ;
    USE SIGNAL ;
    PORT
      LAYER M4 ;
        RECT  0 16.704 0.192 16.728 ;
    END
  END o0[70]
  PIN o0[71]
    DIRECTION OUTPUT ;
    USE SIGNAL ;
    PORT
      LAYER M4 ;
        RECT  0 16.896 0.192 16.92 ;
    END
  END o0[71]
  PIN o0[72]
    DIRECTION OUTPUT ;
    USE SIGNAL ;
    PORT
      LAYER M4 ;
        RECT  0 17.088 0.192 17.112 ;
    END
  END o0[72]
  PIN o0[73]
    DIRECTION OUTPUT ;
    USE SIGNAL ;
    PORT
      LAYER M4 ;
        RECT  0 17.232 0.192 17.256 ;
    END
  END o0[73]
  PIN o0[74]
    DIRECTION OUTPUT ;
    USE SIGNAL ;
    PORT
      LAYER M4 ;
        RECT  0 17.424 0.192 17.448 ;
    END
  END o0[74]
  PIN o0[75]
    DIRECTION OUTPUT ;
    USE SIGNAL ;
    PORT
      LAYER M4 ;
        RECT  0 17.568 0.192 17.592 ;
    END
  END o0[75]
  PIN o0[76]
    DIRECTION OUTPUT ;
    USE SIGNAL ;
    PORT
      LAYER M4 ;
        RECT  0 17.76 0.192 17.784 ;
    END
  END o0[76]
  PIN o0[77]
    DIRECTION OUTPUT ;
    USE SIGNAL ;
    PORT
      LAYER M4 ;
        RECT  0 17.952 0.192 17.976 ;
    END
  END o0[77]
  PIN o0[78]
    DIRECTION OUTPUT ;
    USE SIGNAL ;
    PORT
      LAYER M4 ;
        RECT  0 18.096 0.192 18.12 ;
    END
  END o0[78]
  PIN o0[79]
    DIRECTION OUTPUT ;
    USE SIGNAL ;
    PORT
      LAYER M4 ;
        RECT  0 18.288 0.192 18.312 ;
    END
  END o0[79]
  PIN o0[7]
    DIRECTION OUTPUT ;
    USE SIGNAL ;
    PORT
      LAYER M4 ;
        RECT  0 5.712 0.192 5.736 ;
    END
  END o0[7]
  PIN o0[80]
    DIRECTION OUTPUT ;
    USE SIGNAL ;
    PORT
      LAYER M4 ;
        RECT  0 18.432 0.192 18.456 ;
    END
  END o0[80]
  PIN o0[81]
    DIRECTION OUTPUT ;
    USE SIGNAL ;
    PORT
      LAYER M4 ;
        RECT  0 18.624 0.192 18.648 ;
    END
  END o0[81]
  PIN o0[82]
    DIRECTION OUTPUT ;
    USE SIGNAL ;
    PORT
      LAYER M4 ;
        RECT  0 18.768 0.192 18.792 ;
    END
  END o0[82]
  PIN o0[83]
    DIRECTION OUTPUT ;
    USE SIGNAL ;
    PORT
      LAYER M4 ;
        RECT  0 18.96 0.192 18.984 ;
    END
  END o0[83]
  PIN o0[84]
    DIRECTION OUTPUT ;
    USE SIGNAL ;
    PORT
      LAYER M4 ;
        RECT  0 19.152 0.192 19.176 ;
    END
  END o0[84]
  PIN o0[85]
    DIRECTION OUTPUT ;
    USE SIGNAL ;
    PORT
      LAYER M4 ;
        RECT  0 19.296 0.192 19.32 ;
    END
  END o0[85]
  PIN o0[86]
    DIRECTION OUTPUT ;
    USE SIGNAL ;
    PORT
      LAYER M4 ;
        RECT  0 19.488 0.192 19.512 ;
    END
  END o0[86]
  PIN o0[87]
    DIRECTION OUTPUT ;
    USE SIGNAL ;
    PORT
      LAYER M4 ;
        RECT  0 19.632 0.192 19.656 ;
    END
  END o0[87]
  PIN o0[88]
    DIRECTION OUTPUT ;
    USE SIGNAL ;
    PORT
      LAYER M4 ;
        RECT  0 19.824 0.192 19.848 ;
    END
  END o0[88]
  PIN o0[89]
    DIRECTION OUTPUT ;
    USE SIGNAL ;
    PORT
      LAYER M4 ;
        RECT  0 19.968 0.192 19.992 ;
    END
  END o0[89]
  PIN o0[8]
    DIRECTION OUTPUT ;
    USE SIGNAL ;
    PORT
      LAYER M4 ;
        RECT  0 5.904 0.192 5.928 ;
    END
  END o0[8]
  PIN o0[90]
    DIRECTION OUTPUT ;
    USE SIGNAL ;
    PORT
      LAYER M4 ;
        RECT  0 20.16 0.192 20.184 ;
    END
  END o0[90]
  PIN o0[91]
    DIRECTION OUTPUT ;
    USE SIGNAL ;
    PORT
      LAYER M4 ;
        RECT  0 20.352 0.192 20.376 ;
    END
  END o0[91]
  PIN o0[92]
    DIRECTION OUTPUT ;
    USE SIGNAL ;
    PORT
      LAYER M4 ;
        RECT  0 20.496 0.192 20.52 ;
    END
  END o0[92]
  PIN o0[93]
    DIRECTION OUTPUT ;
    USE SIGNAL ;
    PORT
      LAYER M4 ;
        RECT  0 20.688 0.192 20.712 ;
    END
  END o0[93]
  PIN o0[94]
    DIRECTION OUTPUT ;
    USE SIGNAL ;
    PORT
      LAYER M4 ;
        RECT  0 20.832 0.192 20.856 ;
    END
  END o0[94]
  PIN o0[95]
    DIRECTION OUTPUT ;
    USE SIGNAL ;
    PORT
      LAYER M4 ;
        RECT  0 21.024 0.192 21.048 ;
    END
  END o0[95]
  PIN o0[96]
    DIRECTION OUTPUT ;
    USE SIGNAL ;
    PORT
      LAYER M4 ;
        RECT  0 21.216 0.192 21.24 ;
    END
  END o0[96]
  PIN o0[97]
    DIRECTION OUTPUT ;
    USE SIGNAL ;
    PORT
      LAYER M4 ;
        RECT  0 21.36 0.192 21.384 ;
    END
  END o0[97]
  PIN o0[98]
    DIRECTION OUTPUT ;
    USE SIGNAL ;
    PORT
      LAYER M4 ;
        RECT  0 21.552 0.192 21.576 ;
    END
  END o0[98]
  PIN o0[99]
    DIRECTION OUTPUT ;
    USE SIGNAL ;
    PORT
      LAYER M4 ;
        RECT  0 21.696 0.192 21.72 ;
    END
  END o0[99]
  PIN o0[9]
    DIRECTION OUTPUT ;
    USE SIGNAL ;
    PORT
      LAYER M4 ;
        RECT  0 6.096 0.192 6.12 ;
    END
  END o0[9]
  PIN o1[0]
    DIRECTION OUTPUT ;
    USE SIGNAL ;
    PORT
      LAYER M4 ;
        RECT  0 28.272 0.192 28.296 ;
    END
  END o1[0]
  PIN o1[100]
    DIRECTION OUTPUT ;
    USE SIGNAL ;
    PORT
      LAYER M4 ;
        RECT  0 45.648 0.192 45.672 ;
    END
  END o1[100]
  PIN o1[101]
    DIRECTION OUTPUT ;
    USE SIGNAL ;
    PORT
      LAYER M4 ;
        RECT  0 45.792 0.192 45.816 ;
    END
  END o1[101]
  PIN o1[102]
    DIRECTION OUTPUT ;
    USE SIGNAL ;
    PORT
      LAYER M4 ;
        RECT  0 45.984 0.192 46.008 ;
    END
  END o1[102]
  PIN o1[103]
    DIRECTION OUTPUT ;
    USE SIGNAL ;
    PORT
      LAYER M4 ;
        RECT  0 46.176 0.192 46.2 ;
    END
  END o1[103]
  PIN o1[104]
    DIRECTION OUTPUT ;
    USE SIGNAL ;
    PORT
      LAYER M4 ;
        RECT  0 46.32 0.192 46.344 ;
    END
  END o1[104]
  PIN o1[105]
    DIRECTION OUTPUT ;
    USE SIGNAL ;
    PORT
      LAYER M4 ;
        RECT  0 46.512 0.192 46.536 ;
    END
  END o1[105]
  PIN o1[106]
    DIRECTION OUTPUT ;
    USE SIGNAL ;
    PORT
      LAYER M4 ;
        RECT  0 46.656 0.192 46.68 ;
    END
  END o1[106]
  PIN o1[107]
    DIRECTION OUTPUT ;
    USE SIGNAL ;
    PORT
      LAYER M4 ;
        RECT  0 46.848 0.192 46.872 ;
    END
  END o1[107]
  PIN o1[108]
    DIRECTION OUTPUT ;
    USE SIGNAL ;
    PORT
      LAYER M4 ;
        RECT  0 46.992 0.192 47.016 ;
    END
  END o1[108]
  PIN o1[109]
    DIRECTION OUTPUT ;
    USE SIGNAL ;
    PORT
      LAYER M4 ;
        RECT  0 47.184 0.192 47.208 ;
    END
  END o1[109]
  PIN o1[10]
    DIRECTION OUTPUT ;
    USE SIGNAL ;
    PORT
      LAYER M4 ;
        RECT  0 30 0.192 30.024 ;
    END
  END o1[10]
  PIN o1[110]
    DIRECTION OUTPUT ;
    USE SIGNAL ;
    PORT
      LAYER M4 ;
        RECT  0 47.376 0.192 47.4 ;
    END
  END o1[110]
  PIN o1[111]
    DIRECTION OUTPUT ;
    USE SIGNAL ;
    PORT
      LAYER M4 ;
        RECT  0 47.52 0.192 47.544 ;
    END
  END o1[111]
  PIN o1[112]
    DIRECTION OUTPUT ;
    USE SIGNAL ;
    PORT
      LAYER M4 ;
        RECT  0 47.712 0.192 47.736 ;
    END
  END o1[112]
  PIN o1[113]
    DIRECTION OUTPUT ;
    USE SIGNAL ;
    PORT
      LAYER M4 ;
        RECT  0 47.856 0.192 47.88 ;
    END
  END o1[113]
  PIN o1[114]
    DIRECTION OUTPUT ;
    USE SIGNAL ;
    PORT
      LAYER M4 ;
        RECT  0 48.048 0.192 48.072 ;
    END
  END o1[114]
  PIN o1[115]
    DIRECTION OUTPUT ;
    USE SIGNAL ;
    PORT
      LAYER M4 ;
        RECT  0 48.24 0.192 48.264 ;
    END
  END o1[115]
  PIN o1[116]
    DIRECTION OUTPUT ;
    USE SIGNAL ;
    PORT
      LAYER M4 ;
        RECT  0 48.384 0.192 48.408 ;
    END
  END o1[116]
  PIN o1[117]
    DIRECTION OUTPUT ;
    USE SIGNAL ;
    PORT
      LAYER M4 ;
        RECT  0 48.576 0.192 48.6 ;
    END
  END o1[117]
  PIN o1[118]
    DIRECTION OUTPUT ;
    USE SIGNAL ;
    PORT
      LAYER M4 ;
        RECT  0 48.72 0.192 48.744 ;
    END
  END o1[118]
  PIN o1[119]
    DIRECTION OUTPUT ;
    USE SIGNAL ;
    PORT
      LAYER M4 ;
        RECT  0 48.912 0.192 48.936 ;
    END
  END o1[119]
  PIN o1[11]
    DIRECTION OUTPUT ;
    USE SIGNAL ;
    PORT
      LAYER M4 ;
        RECT  0 30.192 0.192 30.216 ;
    END
  END o1[11]
  PIN o1[120]
    DIRECTION OUTPUT ;
    USE SIGNAL ;
    PORT
      LAYER M4 ;
        RECT  0 49.056 0.192 49.08 ;
    END
  END o1[120]
  PIN o1[121]
    DIRECTION OUTPUT ;
    USE SIGNAL ;
    PORT
      LAYER M4 ;
        RECT  0 49.248 0.192 49.272 ;
    END
  END o1[121]
  PIN o1[122]
    DIRECTION OUTPUT ;
    USE SIGNAL ;
    PORT
      LAYER M4 ;
        RECT  0 49.44 0.192 49.464 ;
    END
  END o1[122]
  PIN o1[123]
    DIRECTION OUTPUT ;
    USE SIGNAL ;
    PORT
      LAYER M4 ;
        RECT  0 49.584 0.192 49.608 ;
    END
  END o1[123]
  PIN o1[124]
    DIRECTION OUTPUT ;
    USE SIGNAL ;
    PORT
      LAYER M4 ;
        RECT  0 49.776 0.192 49.8 ;
    END
  END o1[124]
  PIN o1[125]
    DIRECTION OUTPUT ;
    USE SIGNAL ;
    PORT
      LAYER M4 ;
        RECT  0 49.92 0.192 49.944 ;
    END
  END o1[125]
  PIN o1[126]
    DIRECTION OUTPUT ;
    USE SIGNAL ;
    PORT
      LAYER M4 ;
        RECT  0 50.112 0.192 50.136 ;
    END
  END o1[126]
  PIN o1[127]
    DIRECTION OUTPUT ;
    USE SIGNAL ;
    PORT
      LAYER M4 ;
        RECT  0 50.256 0.192 50.28 ;
    END
  END o1[127]
  PIN o1[128]
    DIRECTION OUTPUT ;
    USE SIGNAL ;
    PORT
      LAYER M4 ;
        RECT  0 50.448 0.192 50.472 ;
    END
  END o1[128]
  PIN o1[129]
    DIRECTION OUTPUT ;
    USE SIGNAL ;
    PORT
      LAYER M4 ;
        RECT  0 50.64 0.192 50.664 ;
    END
  END o1[129]
  PIN o1[12]
    DIRECTION OUTPUT ;
    USE SIGNAL ;
    PORT
      LAYER M4 ;
        RECT  0 30.336 0.192 30.36 ;
    END
  END o1[12]
  PIN o1[130]
    DIRECTION OUTPUT ;
    USE SIGNAL ;
    PORT
      LAYER M4 ;
        RECT  0 50.784 0.192 50.808 ;
    END
  END o1[130]
  PIN o1[131]
    DIRECTION OUTPUT ;
    USE SIGNAL ;
    PORT
      LAYER M4 ;
        RECT  0 50.976 0.192 51 ;
    END
  END o1[131]
  PIN o1[132]
    DIRECTION OUTPUT ;
    USE SIGNAL ;
    PORT
      LAYER M4 ;
        RECT  0 51.12 0.192 51.144 ;
    END
  END o1[132]
  PIN o1[133]
    DIRECTION OUTPUT ;
    USE SIGNAL ;
    PORT
      LAYER M4 ;
        RECT  0 51.312 0.192 51.336 ;
    END
  END o1[133]
  PIN o1[134]
    DIRECTION OUTPUT ;
    USE SIGNAL ;
    PORT
      LAYER M4 ;
        RECT  0 51.504 0.192 51.528 ;
    END
  END o1[134]
  PIN o1[135]
    DIRECTION OUTPUT ;
    USE SIGNAL ;
    PORT
      LAYER M4 ;
        RECT  0 51.648 0.192 51.672 ;
    END
  END o1[135]
  PIN o1[13]
    DIRECTION OUTPUT ;
    USE SIGNAL ;
    PORT
      LAYER M4 ;
        RECT  0 30.528 0.192 30.552 ;
    END
  END o1[13]
  PIN o1[14]
    DIRECTION OUTPUT ;
    USE SIGNAL ;
    PORT
      LAYER M4 ;
        RECT  0 30.72 0.192 30.744 ;
    END
  END o1[14]
  PIN o1[15]
    DIRECTION OUTPUT ;
    USE SIGNAL ;
    PORT
      LAYER M4 ;
        RECT  0 30.864 0.192 30.888 ;
    END
  END o1[15]
  PIN o1[16]
    DIRECTION OUTPUT ;
    USE SIGNAL ;
    PORT
      LAYER M4 ;
        RECT  0 31.056 0.192 31.08 ;
    END
  END o1[16]
  PIN o1[17]
    DIRECTION OUTPUT ;
    USE SIGNAL ;
    PORT
      LAYER M4 ;
        RECT  0 31.2 0.192 31.224 ;
    END
  END o1[17]
  PIN o1[18]
    DIRECTION OUTPUT ;
    USE SIGNAL ;
    PORT
      LAYER M4 ;
        RECT  0 31.392 0.192 31.416 ;
    END
  END o1[18]
  PIN o1[19]
    DIRECTION OUTPUT ;
    USE SIGNAL ;
    PORT
      LAYER M4 ;
        RECT  0 31.536 0.192 31.56 ;
    END
  END o1[19]
  PIN o1[1]
    DIRECTION OUTPUT ;
    USE SIGNAL ;
    PORT
      LAYER M4 ;
        RECT  0 28.464 0.192 28.488 ;
    END
  END o1[1]
  PIN o1[20]
    DIRECTION OUTPUT ;
    USE SIGNAL ;
    PORT
      LAYER M4 ;
        RECT  0 31.728 0.192 31.752 ;
    END
  END o1[20]
  PIN o1[21]
    DIRECTION OUTPUT ;
    USE SIGNAL ;
    PORT
      LAYER M4 ;
        RECT  0 31.92 0.192 31.944 ;
    END
  END o1[21]
  PIN o1[22]
    DIRECTION OUTPUT ;
    USE SIGNAL ;
    PORT
      LAYER M4 ;
        RECT  0 32.064 0.192 32.088 ;
    END
  END o1[22]
  PIN o1[23]
    DIRECTION OUTPUT ;
    USE SIGNAL ;
    PORT
      LAYER M4 ;
        RECT  0 32.256 0.192 32.28 ;
    END
  END o1[23]
  PIN o1[24]
    DIRECTION OUTPUT ;
    USE SIGNAL ;
    PORT
      LAYER M4 ;
        RECT  0 32.4 0.192 32.424 ;
    END
  END o1[24]
  PIN o1[25]
    DIRECTION OUTPUT ;
    USE SIGNAL ;
    PORT
      LAYER M4 ;
        RECT  0 32.592 0.192 32.616 ;
    END
  END o1[25]
  PIN o1[26]
    DIRECTION OUTPUT ;
    USE SIGNAL ;
    PORT
      LAYER M4 ;
        RECT  0 32.736 0.192 32.76 ;
    END
  END o1[26]
  PIN o1[27]
    DIRECTION OUTPUT ;
    USE SIGNAL ;
    PORT
      LAYER M4 ;
        RECT  0 32.928 0.192 32.952 ;
    END
  END o1[27]
  PIN o1[28]
    DIRECTION OUTPUT ;
    USE SIGNAL ;
    PORT
      LAYER M4 ;
        RECT  0 33.12 0.192 33.144 ;
    END
  END o1[28]
  PIN o1[29]
    DIRECTION OUTPUT ;
    USE SIGNAL ;
    PORT
      LAYER M4 ;
        RECT  0 33.264 0.192 33.288 ;
    END
  END o1[29]
  PIN o1[2]
    DIRECTION OUTPUT ;
    USE SIGNAL ;
    PORT
      LAYER M4 ;
        RECT  0 28.656 0.192 28.68 ;
    END
  END o1[2]
  PIN o1[30]
    DIRECTION OUTPUT ;
    USE SIGNAL ;
    PORT
      LAYER M4 ;
        RECT  0 33.456 0.192 33.48 ;
    END
  END o1[30]
  PIN o1[31]
    DIRECTION OUTPUT ;
    USE SIGNAL ;
    PORT
      LAYER M4 ;
        RECT  0 33.6 0.192 33.624 ;
    END
  END o1[31]
  PIN o1[32]
    DIRECTION OUTPUT ;
    USE SIGNAL ;
    PORT
      LAYER M4 ;
        RECT  0 33.792 0.192 33.816 ;
    END
  END o1[32]
  PIN o1[33]
    DIRECTION OUTPUT ;
    USE SIGNAL ;
    PORT
      LAYER M4 ;
        RECT  0 33.984 0.192 34.008 ;
    END
  END o1[33]
  PIN o1[34]
    DIRECTION OUTPUT ;
    USE SIGNAL ;
    PORT
      LAYER M4 ;
        RECT  0 34.128 0.192 34.152 ;
    END
  END o1[34]
  PIN o1[35]
    DIRECTION OUTPUT ;
    USE SIGNAL ;
    PORT
      LAYER M4 ;
        RECT  0 34.32 0.192 34.344 ;
    END
  END o1[35]
  PIN o1[36]
    DIRECTION OUTPUT ;
    USE SIGNAL ;
    PORT
      LAYER M4 ;
        RECT  0 34.464 0.192 34.488 ;
    END
  END o1[36]
  PIN o1[37]
    DIRECTION OUTPUT ;
    USE SIGNAL ;
    PORT
      LAYER M4 ;
        RECT  0 34.656 0.192 34.68 ;
    END
  END o1[37]
  PIN o1[38]
    DIRECTION OUTPUT ;
    USE SIGNAL ;
    PORT
      LAYER M4 ;
        RECT  0 34.8 0.192 34.824 ;
    END
  END o1[38]
  PIN o1[39]
    DIRECTION OUTPUT ;
    USE SIGNAL ;
    PORT
      LAYER M4 ;
        RECT  0 34.992 0.192 35.016 ;
    END
  END o1[39]
  PIN o1[3]
    DIRECTION OUTPUT ;
    USE SIGNAL ;
    PORT
      LAYER M4 ;
        RECT  0 28.8 0.192 28.824 ;
    END
  END o1[3]
  PIN o1[40]
    DIRECTION OUTPUT ;
    USE SIGNAL ;
    PORT
      LAYER M4 ;
        RECT  0 35.184 0.192 35.208 ;
    END
  END o1[40]
  PIN o1[41]
    DIRECTION OUTPUT ;
    USE SIGNAL ;
    PORT
      LAYER M4 ;
        RECT  0 35.328 0.192 35.352 ;
    END
  END o1[41]
  PIN o1[42]
    DIRECTION OUTPUT ;
    USE SIGNAL ;
    PORT
      LAYER M4 ;
        RECT  0 35.52 0.192 35.544 ;
    END
  END o1[42]
  PIN o1[43]
    DIRECTION OUTPUT ;
    USE SIGNAL ;
    PORT
      LAYER M4 ;
        RECT  0 35.664 0.192 35.688 ;
    END
  END o1[43]
  PIN o1[44]
    DIRECTION OUTPUT ;
    USE SIGNAL ;
    PORT
      LAYER M4 ;
        RECT  0 35.856 0.192 35.88 ;
    END
  END o1[44]
  PIN o1[45]
    DIRECTION OUTPUT ;
    USE SIGNAL ;
    PORT
      LAYER M4 ;
        RECT  0 36 0.192 36.024 ;
    END
  END o1[45]
  PIN o1[46]
    DIRECTION OUTPUT ;
    USE SIGNAL ;
    PORT
      LAYER M4 ;
        RECT  0 36.192 0.192 36.216 ;
    END
  END o1[46]
  PIN o1[47]
    DIRECTION OUTPUT ;
    USE SIGNAL ;
    PORT
      LAYER M4 ;
        RECT  0 36.384 0.192 36.408 ;
    END
  END o1[47]
  PIN o1[48]
    DIRECTION OUTPUT ;
    USE SIGNAL ;
    PORT
      LAYER M4 ;
        RECT  0 36.528 0.192 36.552 ;
    END
  END o1[48]
  PIN o1[49]
    DIRECTION OUTPUT ;
    USE SIGNAL ;
    PORT
      LAYER M4 ;
        RECT  0 36.72 0.192 36.744 ;
    END
  END o1[49]
  PIN o1[4]
    DIRECTION OUTPUT ;
    USE SIGNAL ;
    PORT
      LAYER M4 ;
        RECT  0 28.992 0.192 29.016 ;
    END
  END o1[4]
  PIN o1[50]
    DIRECTION OUTPUT ;
    USE SIGNAL ;
    PORT
      LAYER M4 ;
        RECT  0 36.864 0.192 36.888 ;
    END
  END o1[50]
  PIN o1[51]
    DIRECTION OUTPUT ;
    USE SIGNAL ;
    PORT
      LAYER M4 ;
        RECT  0 37.056 0.192 37.08 ;
    END
  END o1[51]
  PIN o1[52]
    DIRECTION OUTPUT ;
    USE SIGNAL ;
    PORT
      LAYER M4 ;
        RECT  0 37.2 0.192 37.224 ;
    END
  END o1[52]
  PIN o1[53]
    DIRECTION OUTPUT ;
    USE SIGNAL ;
    PORT
      LAYER M4 ;
        RECT  0 37.392 0.192 37.416 ;
    END
  END o1[53]
  PIN o1[54]
    DIRECTION OUTPUT ;
    USE SIGNAL ;
    PORT
      LAYER M4 ;
        RECT  0 37.584 0.192 37.608 ;
    END
  END o1[54]
  PIN o1[55]
    DIRECTION OUTPUT ;
    USE SIGNAL ;
    PORT
      LAYER M4 ;
        RECT  0 37.728 0.192 37.752 ;
    END
  END o1[55]
  PIN o1[56]
    DIRECTION OUTPUT ;
    USE SIGNAL ;
    PORT
      LAYER M4 ;
        RECT  0 37.92 0.192 37.944 ;
    END
  END o1[56]
  PIN o1[57]
    DIRECTION OUTPUT ;
    USE SIGNAL ;
    PORT
      LAYER M4 ;
        RECT  0 38.064 0.192 38.088 ;
    END
  END o1[57]
  PIN o1[58]
    DIRECTION OUTPUT ;
    USE SIGNAL ;
    PORT
      LAYER M4 ;
        RECT  0 38.256 0.192 38.28 ;
    END
  END o1[58]
  PIN o1[59]
    DIRECTION OUTPUT ;
    USE SIGNAL ;
    PORT
      LAYER M4 ;
        RECT  0 38.448 0.192 38.472 ;
    END
  END o1[59]
  PIN o1[5]
    DIRECTION OUTPUT ;
    USE SIGNAL ;
    PORT
      LAYER M4 ;
        RECT  0 29.136 0.192 29.16 ;
    END
  END o1[5]
  PIN o1[60]
    DIRECTION OUTPUT ;
    USE SIGNAL ;
    PORT
      LAYER M4 ;
        RECT  0 38.592 0.192 38.616 ;
    END
  END o1[60]
  PIN o1[61]
    DIRECTION OUTPUT ;
    USE SIGNAL ;
    PORT
      LAYER M4 ;
        RECT  0 38.784 0.192 38.808 ;
    END
  END o1[61]
  PIN o1[62]
    DIRECTION OUTPUT ;
    USE SIGNAL ;
    PORT
      LAYER M4 ;
        RECT  0 38.928 0.192 38.952 ;
    END
  END o1[62]
  PIN o1[63]
    DIRECTION OUTPUT ;
    USE SIGNAL ;
    PORT
      LAYER M4 ;
        RECT  0 39.12 0.192 39.144 ;
    END
  END o1[63]
  PIN o1[64]
    DIRECTION OUTPUT ;
    USE SIGNAL ;
    PORT
      LAYER M4 ;
        RECT  0 39.264 0.192 39.288 ;
    END
  END o1[64]
  PIN o1[65]
    DIRECTION OUTPUT ;
    USE SIGNAL ;
    PORT
      LAYER M4 ;
        RECT  0 39.456 0.192 39.48 ;
    END
  END o1[65]
  PIN o1[66]
    DIRECTION OUTPUT ;
    USE SIGNAL ;
    PORT
      LAYER M4 ;
        RECT  0 39.648 0.192 39.672 ;
    END
  END o1[66]
  PIN o1[67]
    DIRECTION OUTPUT ;
    USE SIGNAL ;
    PORT
      LAYER M4 ;
        RECT  0 39.792 0.192 39.816 ;
    END
  END o1[67]
  PIN o1[68]
    DIRECTION OUTPUT ;
    USE SIGNAL ;
    PORT
      LAYER M4 ;
        RECT  0 40.128 0.192 40.152 ;
    END
  END o1[68]
  PIN o1[69]
    DIRECTION OUTPUT ;
    USE SIGNAL ;
    PORT
      LAYER M4 ;
        RECT  0 40.32 0.192 40.344 ;
    END
  END o1[69]
  PIN o1[6]
    DIRECTION OUTPUT ;
    USE SIGNAL ;
    PORT
      LAYER M4 ;
        RECT  0 29.328 0.192 29.352 ;
    END
  END o1[6]
  PIN o1[70]
    DIRECTION OUTPUT ;
    USE SIGNAL ;
    PORT
      LAYER M4 ;
        RECT  0 40.464 0.192 40.488 ;
    END
  END o1[70]
  PIN o1[71]
    DIRECTION OUTPUT ;
    USE SIGNAL ;
    PORT
      LAYER M4 ;
        RECT  0 40.656 0.192 40.68 ;
    END
  END o1[71]
  PIN o1[72]
    DIRECTION OUTPUT ;
    USE SIGNAL ;
    PORT
      LAYER M4 ;
        RECT  0 40.848 0.192 40.872 ;
    END
  END o1[72]
  PIN o1[73]
    DIRECTION OUTPUT ;
    USE SIGNAL ;
    PORT
      LAYER M4 ;
        RECT  0 40.992 0.192 41.016 ;
    END
  END o1[73]
  PIN o1[74]
    DIRECTION OUTPUT ;
    USE SIGNAL ;
    PORT
      LAYER M4 ;
        RECT  0 41.184 0.192 41.208 ;
    END
  END o1[74]
  PIN o1[75]
    DIRECTION OUTPUT ;
    USE SIGNAL ;
    PORT
      LAYER M4 ;
        RECT  0 41.328 0.192 41.352 ;
    END
  END o1[75]
  PIN o1[76]
    DIRECTION OUTPUT ;
    USE SIGNAL ;
    PORT
      LAYER M4 ;
        RECT  0 41.52 0.192 41.544 ;
    END
  END o1[76]
  PIN o1[77]
    DIRECTION OUTPUT ;
    USE SIGNAL ;
    PORT
      LAYER M4 ;
        RECT  0 41.712 0.192 41.736 ;
    END
  END o1[77]
  PIN o1[78]
    DIRECTION OUTPUT ;
    USE SIGNAL ;
    PORT
      LAYER M4 ;
        RECT  0 41.856 0.192 41.88 ;
    END
  END o1[78]
  PIN o1[79]
    DIRECTION OUTPUT ;
    USE SIGNAL ;
    PORT
      LAYER M4 ;
        RECT  0 42.048 0.192 42.072 ;
    END
  END o1[79]
  PIN o1[7]
    DIRECTION OUTPUT ;
    USE SIGNAL ;
    PORT
      LAYER M4 ;
        RECT  0 29.472 0.192 29.496 ;
    END
  END o1[7]
  PIN o1[80]
    DIRECTION OUTPUT ;
    USE SIGNAL ;
    PORT
      LAYER M4 ;
        RECT  0 42.192 0.192 42.216 ;
    END
  END o1[80]
  PIN o1[81]
    DIRECTION OUTPUT ;
    USE SIGNAL ;
    PORT
      LAYER M4 ;
        RECT  0 42.384 0.192 42.408 ;
    END
  END o1[81]
  PIN o1[82]
    DIRECTION OUTPUT ;
    USE SIGNAL ;
    PORT
      LAYER M4 ;
        RECT  0 42.528 0.192 42.552 ;
    END
  END o1[82]
  PIN o1[83]
    DIRECTION OUTPUT ;
    USE SIGNAL ;
    PORT
      LAYER M4 ;
        RECT  0 42.72 0.192 42.744 ;
    END
  END o1[83]
  PIN o1[84]
    DIRECTION OUTPUT ;
    USE SIGNAL ;
    PORT
      LAYER M4 ;
        RECT  0 42.912 0.192 42.936 ;
    END
  END o1[84]
  PIN o1[85]
    DIRECTION OUTPUT ;
    USE SIGNAL ;
    PORT
      LAYER M4 ;
        RECT  0 43.056 0.192 43.08 ;
    END
  END o1[85]
  PIN o1[86]
    DIRECTION OUTPUT ;
    USE SIGNAL ;
    PORT
      LAYER M4 ;
        RECT  0 43.248 0.192 43.272 ;
    END
  END o1[86]
  PIN o1[87]
    DIRECTION OUTPUT ;
    USE SIGNAL ;
    PORT
      LAYER M4 ;
        RECT  0 43.392 0.192 43.416 ;
    END
  END o1[87]
  PIN o1[88]
    DIRECTION OUTPUT ;
    USE SIGNAL ;
    PORT
      LAYER M4 ;
        RECT  0 43.584 0.192 43.608 ;
    END
  END o1[88]
  PIN o1[89]
    DIRECTION OUTPUT ;
    USE SIGNAL ;
    PORT
      LAYER M4 ;
        RECT  0 43.728 0.192 43.752 ;
    END
  END o1[89]
  PIN o1[8]
    DIRECTION OUTPUT ;
    USE SIGNAL ;
    PORT
      LAYER M4 ;
        RECT  0 29.664 0.192 29.688 ;
    END
  END o1[8]
  PIN o1[90]
    DIRECTION OUTPUT ;
    USE SIGNAL ;
    PORT
      LAYER M4 ;
        RECT  0 43.92 0.192 43.944 ;
    END
  END o1[90]
  PIN o1[91]
    DIRECTION OUTPUT ;
    USE SIGNAL ;
    PORT
      LAYER M4 ;
        RECT  0 44.112 0.192 44.136 ;
    END
  END o1[91]
  PIN o1[92]
    DIRECTION OUTPUT ;
    USE SIGNAL ;
    PORT
      LAYER M4 ;
        RECT  0 44.256 0.192 44.28 ;
    END
  END o1[92]
  PIN o1[93]
    DIRECTION OUTPUT ;
    USE SIGNAL ;
    PORT
      LAYER M4 ;
        RECT  0 44.448 0.192 44.472 ;
    END
  END o1[93]
  PIN o1[94]
    DIRECTION OUTPUT ;
    USE SIGNAL ;
    PORT
      LAYER M4 ;
        RECT  0 44.592 0.192 44.616 ;
    END
  END o1[94]
  PIN o1[95]
    DIRECTION OUTPUT ;
    USE SIGNAL ;
    PORT
      LAYER M4 ;
        RECT  0 44.784 0.192 44.808 ;
    END
  END o1[95]
  PIN o1[96]
    DIRECTION OUTPUT ;
    USE SIGNAL ;
    PORT
      LAYER M4 ;
        RECT  0 44.976 0.192 45 ;
    END
  END o1[96]
  PIN o1[97]
    DIRECTION OUTPUT ;
    USE SIGNAL ;
    PORT
      LAYER M4 ;
        RECT  0 45.12 0.192 45.144 ;
    END
  END o1[97]
  PIN o1[98]
    DIRECTION OUTPUT ;
    USE SIGNAL ;
    PORT
      LAYER M4 ;
        RECT  0 45.312 0.192 45.336 ;
    END
  END o1[98]
  PIN o1[99]
    DIRECTION OUTPUT ;
    USE SIGNAL ;
    PORT
      LAYER M4 ;
        RECT  0 45.456 0.192 45.48 ;
    END
  END o1[99]
  PIN o1[9]
    DIRECTION OUTPUT ;
    USE SIGNAL ;
    PORT
      LAYER M4 ;
        RECT  0 29.856 0.192 29.88 ;
    END
  END o1[9]
  PIN rs
    DIRECTION INPUT ;
    USE SIGNAL ;
    PORT
      LAYER M5 ;
        RECT  10.8 0 10.824 0.192 ;
    END
  END rs
  PIN VDD
    DIRECTION INOUT ;
    USE POWER ;
    PORT
      LAYER M5 ;
        RECT  18.792 2.151 18.912 54.009 ;
        RECT  16.092 2.151 16.212 54.009 ;
        RECT  13.392 2.151 13.512 54.009 ;
        RECT  10.692 2.151 10.812 54.009 ;
        RECT  7.992 2.151 8.112 54.009 ;
        RECT  5.292 2.151 5.412 54.009 ;
        RECT  2.592 2.151 2.712 54.009 ;
    END
  END VDD
  PIN VSS
    DIRECTION INOUT ;
    USE GROUND ;
    PORT
      LAYER M5 ;
        RECT  18.6 2.137 18.72 54.023 ;
        RECT  15.9 2.137 16.02 54.023 ;
        RECT  13.2 2.137 13.32 54.023 ;
        RECT  10.5 2.137 10.62 54.023 ;
        RECT  7.8 2.137 7.92 54.023 ;
        RECT  5.1 2.137 5.22 54.023 ;
        RECT  2.4 2.137 2.52 54.023 ;
    END
  END VSS
  OBS
    LAYER RVTN ;
     RECT  2.16 2.16 19.44 2.295 ;
     RECT  2.16 2.565 19.44 2.835 ;
     RECT  2.16 3.105 19.44 3.375 ;
     RECT  2.16 3.645 19.44 3.915 ;
     RECT  2.16 4.185 19.44 4.455 ;
     RECT  2.16 4.725 19.44 4.995 ;
     RECT  2.16 5.265 19.44 5.535 ;
     RECT  2.16 5.805 19.44 6.075 ;
     RECT  2.16 6.345 19.44 6.615 ;
     RECT  2.16 6.885 19.44 7.155 ;
     RECT  2.16 7.425 19.44 7.695 ;
     RECT  2.16 7.965 19.44 8.235 ;
     RECT  2.16 8.505 19.44 8.775 ;
     RECT  2.16 9.045 19.44 9.315 ;
     RECT  2.16 9.585 19.44 9.855 ;
     RECT  2.16 10.125 19.44 10.395 ;
     RECT  2.16 10.665 19.44 10.935 ;
     RECT  2.16 11.205 19.44 11.475 ;
     RECT  2.16 11.745 19.44 12.015 ;
     RECT  2.16 12.285 19.44 12.555 ;
     RECT  2.16 12.825 19.44 13.095 ;
     RECT  2.16 13.365 19.44 13.635 ;
     RECT  2.16 13.905 19.44 14.175 ;
     RECT  2.16 14.445 19.44 14.715 ;
     RECT  2.16 14.985 19.44 15.255 ;
     RECT  2.16 15.525 19.44 15.795 ;
     RECT  2.16 16.065 19.44 16.335 ;
     RECT  2.16 16.605 19.44 16.875 ;
     RECT  2.16 17.145 19.44 17.415 ;
     RECT  2.16 17.685 19.44 17.955 ;
     RECT  2.16 18.225 19.44 18.495 ;
     RECT  2.16 18.765 19.44 19.035 ;
     RECT  2.16 19.305 19.44 19.575 ;
     RECT  2.16 19.845 19.44 20.115 ;
     RECT  2.16 20.385 19.44 20.655 ;
     RECT  2.16 20.925 19.44 21.195 ;
     RECT  2.16 21.465 19.44 21.735 ;
     RECT  2.16 22.005 19.44 22.275 ;
     RECT  2.16 22.545 19.44 22.815 ;
     RECT  2.16 23.085 19.44 23.355 ;
     RECT  2.16 23.625 19.44 23.895 ;
     RECT  2.16 24.165 19.44 24.435 ;
     RECT  2.16 24.705 19.44 24.975 ;
     RECT  2.16 25.245 19.44 25.515 ;
     RECT  2.16 25.785 19.44 26.055 ;
     RECT  2.16 26.325 19.44 26.595 ;
     RECT  2.16 26.865 19.44 27.135 ;
     RECT  2.16 27.405 19.44 27.675 ;
     RECT  2.16 27.945 19.44 28.215 ;
     RECT  2.16 28.485 19.44 28.755 ;
     RECT  2.16 29.025 19.44 29.295 ;
     RECT  2.16 29.565 19.44 29.835 ;
     RECT  2.16 30.105 19.44 30.375 ;
     RECT  2.16 30.645 19.44 30.915 ;
     RECT  2.16 31.185 19.44 31.455 ;
     RECT  2.16 31.725 19.44 31.995 ;
     RECT  2.16 32.265 19.44 32.535 ;
     RECT  2.16 32.805 19.44 33.075 ;
     RECT  2.16 33.345 19.44 33.615 ;
     RECT  2.16 33.885 19.44 34.155 ;
     RECT  2.16 34.425 19.44 34.695 ;
     RECT  2.16 34.965 19.44 35.235 ;
     RECT  2.16 35.505 19.44 35.775 ;
     RECT  2.16 36.045 19.44 36.315 ;
     RECT  2.16 36.585 19.44 36.855 ;
     RECT  2.16 37.125 19.44 37.395 ;
     RECT  2.16 37.665 19.44 37.935 ;
     RECT  2.16 38.205 19.44 38.475 ;
     RECT  2.16 38.745 19.44 39.015 ;
     RECT  2.16 39.285 19.44 39.555 ;
     RECT  2.16 39.825 19.44 40.095 ;
     RECT  2.16 40.365 19.44 40.635 ;
     RECT  2.16 40.905 19.44 41.175 ;
     RECT  2.16 41.445 19.44 41.715 ;
     RECT  2.16 41.985 19.44 42.255 ;
     RECT  2.16 42.525 19.44 42.795 ;
     RECT  2.16 43.065 19.44 43.335 ;
     RECT  2.16 43.605 19.44 43.875 ;
     RECT  2.16 44.145 19.44 44.415 ;
     RECT  2.16 44.685 19.44 44.955 ;
     RECT  2.16 45.225 19.44 45.495 ;
     RECT  2.16 45.765 19.44 46.035 ;
     RECT  2.16 46.305 19.44 46.575 ;
     RECT  2.16 46.845 19.44 47.115 ;
     RECT  2.16 47.385 19.44 47.655 ;
     RECT  2.16 47.925 19.44 48.195 ;
     RECT  2.16 48.465 19.44 48.735 ;
     RECT  2.16 49.005 19.44 49.275 ;
     RECT  2.16 49.545 19.44 49.815 ;
     RECT  2.16 50.085 19.44 50.355 ;
     RECT  2.16 50.625 19.44 50.895 ;
     RECT  2.16 51.165 19.44 51.435 ;
     RECT  2.16 51.705 19.44 51.975 ;
     RECT  2.16 52.245 19.44 52.515 ;
     RECT  2.16 52.785 19.44 53.055 ;
     RECT  2.16 53.325 19.44 53.595 ;
     RECT  2.16 53.865 19.44 54 ;
    LAYER RVTP ;
     RECT  2.16 2.295 19.44 2.565 ;
     RECT  2.16 2.835 19.44 3.105 ;
     RECT  2.16 3.375 19.44 3.645 ;
     RECT  2.16 3.915 19.44 4.185 ;
     RECT  2.16 4.455 19.44 4.725 ;
     RECT  2.16 4.995 19.44 5.265 ;
     RECT  2.16 5.535 19.44 5.805 ;
     RECT  2.16 6.075 19.44 6.345 ;
     RECT  2.16 6.615 19.44 6.885 ;
     RECT  2.16 7.155 19.44 7.425 ;
     RECT  2.16 7.695 19.44 7.965 ;
     RECT  2.16 8.235 19.44 8.505 ;
     RECT  2.16 8.775 19.44 9.045 ;
     RECT  2.16 9.315 19.44 9.585 ;
     RECT  2.16 9.855 19.44 10.125 ;
     RECT  2.16 10.395 19.44 10.665 ;
     RECT  2.16 10.935 19.44 11.205 ;
     RECT  2.16 11.475 19.44 11.745 ;
     RECT  2.16 12.015 19.44 12.285 ;
     RECT  2.16 12.555 19.44 12.825 ;
     RECT  2.16 13.095 19.44 13.365 ;
     RECT  2.16 13.635 19.44 13.905 ;
     RECT  2.16 14.175 19.44 14.445 ;
     RECT  2.16 14.715 19.44 14.985 ;
     RECT  2.16 15.255 19.44 15.525 ;
     RECT  2.16 15.795 19.44 16.065 ;
     RECT  2.16 16.335 19.44 16.605 ;
     RECT  2.16 16.875 19.44 17.145 ;
     RECT  2.16 17.415 19.44 17.685 ;
     RECT  2.16 17.955 19.44 18.225 ;
     RECT  2.16 18.495 19.44 18.765 ;
     RECT  2.16 19.035 19.44 19.305 ;
     RECT  2.16 19.575 19.44 19.845 ;
     RECT  2.16 20.115 19.44 20.385 ;
     RECT  2.16 20.655 19.44 20.925 ;
     RECT  2.16 21.195 19.44 21.465 ;
     RECT  2.16 21.735 19.44 22.005 ;
     RECT  2.16 22.275 19.44 22.545 ;
     RECT  2.16 22.815 19.44 23.085 ;
     RECT  2.16 23.355 19.44 23.625 ;
     RECT  2.16 23.895 19.44 24.165 ;
     RECT  2.16 24.435 19.44 24.705 ;
     RECT  2.16 24.975 19.44 25.245 ;
     RECT  2.16 25.515 19.44 25.785 ;
     RECT  2.16 26.055 19.44 26.325 ;
     RECT  2.16 26.595 19.44 26.865 ;
     RECT  2.16 27.135 19.44 27.405 ;
     RECT  2.16 27.675 19.44 27.945 ;
     RECT  2.16 28.215 19.44 28.485 ;
     RECT  2.16 28.755 19.44 29.025 ;
     RECT  2.16 29.295 19.44 29.565 ;
     RECT  2.16 29.835 19.44 30.105 ;
     RECT  2.16 30.375 19.44 30.645 ;
     RECT  2.16 30.915 19.44 31.185 ;
     RECT  2.16 31.455 19.44 31.725 ;
     RECT  2.16 31.995 19.44 32.265 ;
     RECT  2.16 32.535 19.44 32.805 ;
     RECT  2.16 33.075 19.44 33.345 ;
     RECT  2.16 33.615 19.44 33.885 ;
     RECT  2.16 34.155 19.44 34.425 ;
     RECT  2.16 34.695 19.44 34.965 ;
     RECT  2.16 35.235 19.44 35.505 ;
     RECT  2.16 35.775 19.44 36.045 ;
     RECT  2.16 36.315 19.44 36.585 ;
     RECT  2.16 36.855 19.44 37.125 ;
     RECT  2.16 37.395 19.44 37.665 ;
     RECT  2.16 37.935 19.44 38.205 ;
     RECT  2.16 38.475 19.44 38.745 ;
     RECT  2.16 39.015 19.44 39.285 ;
     RECT  2.16 39.555 19.44 39.825 ;
     RECT  2.16 40.095 19.44 40.365 ;
     RECT  2.16 40.635 19.44 40.905 ;
     RECT  2.16 41.175 19.44 41.445 ;
     RECT  2.16 41.715 19.44 41.985 ;
     RECT  2.16 42.255 19.44 42.525 ;
     RECT  2.16 42.795 19.44 43.065 ;
     RECT  2.16 43.335 19.44 43.605 ;
     RECT  2.16 43.875 19.44 44.145 ;
     RECT  2.16 44.415 19.44 44.685 ;
     RECT  2.16 44.955 19.44 45.225 ;
     RECT  2.16 45.495 19.44 45.765 ;
     RECT  2.16 46.035 19.44 46.305 ;
     RECT  2.16 46.575 19.44 46.845 ;
     RECT  2.16 47.115 19.44 47.385 ;
     RECT  2.16 47.655 19.44 47.925 ;
     RECT  2.16 48.195 19.44 48.465 ;
     RECT  2.16 48.735 19.44 49.005 ;
     RECT  2.16 49.275 19.44 49.545 ;
     RECT  2.16 49.815 19.44 50.085 ;
     RECT  2.16 50.355 19.44 50.625 ;
     RECT  2.16 50.895 19.44 51.165 ;
     RECT  2.16 51.435 19.44 51.705 ;
     RECT  2.16 51.975 19.44 52.245 ;
     RECT  2.16 52.515 19.44 52.785 ;
     RECT  2.16 53.055 19.44 53.325 ;
     RECT  2.16 53.595 19.44 53.865 ;
    LAYER M1 ;
     RECT  2.16 2.151 19.44 54.009 ;
    LAYER M2 ;
     RECT  0.031 20.124 0.067 20.142 ;
     RECT  0.031 21.096 0.103 21.564 ;
     RECT  0.067 19.818 0.139 20.142 ;
     RECT  0.103 21.096 0.139 22.194 ;
     RECT  0.139 19.818 0.175 22.194 ;
     RECT  0.031 33.048 0.175 33.066 ;
     RECT  0.103 35.586 0.239 35.604 ;
     RECT  0.031 25.101 0.283 25.119 ;
     RECT  0.211 39.096 0.311 39.114 ;
     RECT  0.283 24.948 0.383 25.119 ;
     RECT  0.175 19.35 0.455 22.194 ;
     RECT  0.139 34.74 0.499 34.758 ;
     RECT  0.283 41.346 0.499 41.364 ;
     RECT  0.463 42.966 0.499 42.984 ;
     RECT  0.463 47.394 0.499 47.412 ;
     RECT  0.211 30.006 0.535 30.024 ;
     RECT  0.175 33.048 0.535 33.336 ;
     RECT  0.499 46.746 0.535 48.456 ;
     RECT  0.211 49.824 0.535 49.842 ;
     RECT  0.535 30.888 0.751 30.906 ;
     RECT  0.751 31.896 0.787 31.914 ;
     RECT  0.535 33.048 0.787 33.984 ;
     RECT  0.499 34.74 0.787 35.064 ;
     RECT  0.787 33.048 0.823 35.064 ;
     RECT  0.787 31.806 0.859 31.914 ;
     RECT  0.859 31.734 0.895 31.914 ;
     RECT  0.823 32.814 0.895 35.064 ;
     RECT  0.967 36.126 1.039 36.144 ;
     RECT  0.895 15.066 1.147 15.084 ;
     RECT  0.211 18.126 1.183 18.144 ;
     RECT  0.499 41.22 1.183 42.984 ;
     RECT  0.455 19.35 1.211 20.574 ;
     RECT  1.147 15.066 1.247 15.354 ;
     RECT  1.147 17.046 1.247 17.136 ;
     RECT  0.319 23.328 1.291 23.346 ;
     RECT  0.383 24.948 1.327 24.966 ;
     RECT  1.247 17.046 1.363 17.064 ;
     RECT  0.715 26.406 1.363 26.424 ;
     RECT  0.751 30.816 1.363 30.906 ;
     RECT  0.895 31.698 1.363 35.064 ;
     RECT  1.291 23.058 1.391 23.346 ;
     RECT  1.363 16.344 1.435 17.064 ;
     RECT  1.363 30.816 1.471 35.064 ;
     RECT  1.039 35.856 1.471 36.144 ;
     RECT  0.535 29.376 1.687 30.024 ;
     RECT  1.471 30.816 1.687 36.144 ;
     RECT  1.327 24.876 1.903 24.966 ;
     RECT  0.535 46.746 1.903 50.544 ;
     RECT  1.903 24.876 1.939 25.074 ;
     RECT  1.211 19.818 1.975 20.574 ;
     RECT  0.455 21.636 1.975 22.194 ;
     RECT  0.535 11.376 2.011 11.394 ;
     RECT  0.535 40.446 2.011 40.464 ;
     RECT  1.183 41.22 2.011 43.254 ;
     RECT  0.859 12.906 2.047 12.924 ;
     RECT  1.723 13.716 2.047 13.734 ;
     RECT  1.687 29.376 2.047 36.144 ;
     RECT  0.211 4.266 2.16 4.284 ;
     RECT  0.823 8.514 2.16 8.532 ;
     RECT  2.011 11.376 2.16 11.736 ;
     RECT  2.047 12.906 2.16 13.734 ;
     RECT  1.247 15.066 2.16 15.084 ;
     RECT  1.435 16.074 2.16 17.064 ;
     RECT  1.183 18.036 2.16 18.144 ;
     RECT  1.975 19.818 2.16 22.194 ;
     RECT  1.391 23.058 2.16 23.076 ;
     RECT  1.939 24.444 2.16 25.074 ;
     RECT  1.363 26.406 2.16 26.622 ;
     RECT  2.047 29.376 2.16 36.684 ;
     RECT  1.075 37.476 2.16 37.494 ;
     RECT  1.399 39.456 2.16 39.474 ;
     RECT  2.011 40.446 2.16 43.254 ;
     RECT  0.247 44.424 2.16 44.442 ;
     RECT  0.535 45.306 2.16 45.324 ;
     RECT  1.903 46.206 2.16 50.544 ;
     RECT  2.16 2.151 19.44 54.009 ;
     RECT  19.44 45.738 19.463 50.616 ;
     RECT  19.44 4.698 19.967 5.598 ;
     RECT  19.44 6.39 19.967 6.84 ;
     RECT  19.44 7.74 19.967 15.516 ;
     RECT  19.44 16.38 19.967 16.866 ;
     RECT  19.44 17.658 19.967 20.106 ;
     RECT  19.44 20.97 19.967 24.804 ;
     RECT  19.44 25.758 19.967 25.776 ;
     RECT  19.44 26.64 19.967 27.774 ;
     RECT  19.44 28.728 19.967 28.98 ;
     RECT  19.44 30.078 19.967 35.298 ;
     RECT  19.44 36.09 19.967 39.888 ;
     RECT  19.44 40.68 19.967 41.238 ;
     RECT  19.44 42.3 19.967 44.946 ;
     RECT  19.463 45.738 19.967 47.646 ;
     RECT  19.463 48.708 19.967 50.616 ;
     RECT  19.44 51.48 19.967 52.236 ;
     RECT  19.967 6.588 20.003 6.84 ;
     RECT  19.967 7.938 20.003 7.956 ;
     RECT  19.967 9.63 20.003 10.458 ;
     RECT  19.967 11.826 20.003 12.276 ;
     RECT  19.967 13.068 20.003 13.086 ;
     RECT  19.967 14.22 20.003 15.516 ;
     RECT  19.967 16.578 20.003 16.596 ;
     RECT  19.967 17.658 20.003 18.216 ;
     RECT  19.967 22.212 20.003 22.806 ;
     RECT  19.967 24.714 20.003 24.732 ;
     RECT  19.967 26.838 20.003 26.856 ;
     RECT  19.967 31.23 20.003 31.248 ;
     RECT  19.967 32.346 20.003 32.364 ;
     RECT  19.967 33.354 20.003 33.372 ;
     RECT  19.967 34.398 20.003 34.758 ;
     RECT  19.967 36.36 20.003 36.378 ;
     RECT  19.967 37.368 20.003 37.386 ;
     RECT  19.967 38.682 20.003 39.078 ;
     RECT  19.967 40.95 20.003 41.238 ;
     RECT  19.967 42.498 20.003 44.946 ;
     RECT  19.967 47.088 20.003 47.106 ;
     RECT  19.967 49.518 20.003 49.536 ;
     RECT  19.967 52.218 20.003 52.236 ;
     RECT  20.003 14.418 20.039 14.436 ;
     RECT  20.003 17.658 20.039 17.676 ;
     RECT  20.003 42.498 20.039 42.516 ;
     RECT  20.003 6.822 20.543 6.84 ;
     RECT  20.003 9.63 20.543 9.648 ;
     RECT  19.967 39.87 20.543 39.888 ;
     RECT  20.003 40.95 20.543 40.968 ;
    LAYER M3 ;
     RECT  10.8 1.723 10.818 2.143 ;
     RECT  10.515 2.143 10.818 2.371 ;
     RECT  2.415 2.143 2.505 2.413 ;
     RECT  5.115 2.143 5.205 2.413 ;
     RECT  7.815 2.143 7.905 2.413 ;
     RECT  13.215 2.143 13.305 2.413 ;
     RECT  15.915 2.143 16.005 2.413 ;
     RECT  18.615 2.143 18.705 2.413 ;
     RECT  10.515 2.371 10.998 2.641 ;
     RECT  2.415 2.413 2.697 3.721 ;
     RECT  2.376 3.721 2.862 3.991 ;
     RECT  10.515 2.641 11.214 4.145 ;
     RECT  18.615 2.413 18.897 4.153 ;
     RECT  18.615 4.153 18.99 4.225 ;
     RECT  2.376 3.991 2.97 4.261 ;
     RECT  18.615 4.225 19.098 4.495 ;
     RECT  18.615 4.495 19.242 4.507 ;
     RECT  15.915 2.413 16.197 4.657 ;
     RECT  17.712 4.621 17.73 4.657 ;
     RECT  15.48 4.657 16.197 4.729 ;
     RECT  2.376 4.261 3.366 4.765 ;
     RECT  17.28 4.657 17.73 4.765 ;
     RECT  18.615 4.507 19.962 4.765 ;
     RECT  15.48 4.729 16.29 4.801 ;
     RECT  17.28 4.765 19.962 4.801 ;
     RECT  5.115 2.413 5.397 4.891 ;
     RECT  2.376 4.765 3.546 4.963 ;
     RECT  4.572 4.891 5.397 5.035 ;
     RECT  12.06 4.261 12.078 5.035 ;
     RECT  13.215 2.413 13.497 5.035 ;
     RECT  15.48 4.801 19.962 5.063 ;
     RECT  15.48 5.063 17.478 5.071 ;
     RECT  6.804 4.801 6.822 5.099 ;
     RECT  15.336 5.071 17.478 5.117 ;
     RECT  2.232 4.963 3.546 5.161 ;
     RECT  4.32 5.035 5.397 5.161 ;
     RECT  17.28 5.117 17.478 5.189 ;
     RECT  18.216 5.063 19.962 5.189 ;
     RECT  12.06 5.035 13.497 5.197 ;
     RECT  12.06 5.197 13.698 5.233 ;
     RECT  18.216 5.189 19.098 5.261 ;
     RECT  12.06 5.233 14.274 5.269 ;
     RECT  12.06 5.269 14.562 5.305 ;
     RECT  15.336 5.117 16.29 5.305 ;
     RECT  0.216 4.261 0.234 5.501 ;
     RECT  12.06 5.305 16.29 5.575 ;
     RECT  12.024 5.575 16.29 5.693 ;
     RECT  12.564 5.693 16.29 5.801 ;
     RECT  2.232 5.161 5.397 5.971 ;
     RECT  2.232 5.971 5.634 6.007 ;
     RECT  6.84 5.881 6.858 6.007 ;
     RECT  18.252 5.261 19.026 6.007 ;
     RECT  17.64 6.007 19.026 6.043 ;
     RECT  1.152 5.995 1.17 6.091 ;
     RECT  15.336 5.801 16.29 6.115 ;
     RECT  17.496 6.043 19.026 6.115 ;
     RECT  1.152 6.091 1.278 6.125 ;
     RECT  2.232 6.007 6.858 6.143 ;
     RECT  17.496 6.115 19.098 6.151 ;
     RECT  19.944 5.189 19.962 6.151 ;
     RECT  15.336 6.115 16.614 6.241 ;
     RECT  17.496 6.151 19.962 6.241 ;
     RECT  1.26 6.125 1.278 6.269 ;
     RECT  15.336 6.241 19.962 6.269 ;
     RECT  15.915 6.269 19.962 6.283 ;
     RECT  15.915 6.283 19.998 6.317 ;
     RECT  2.232 6.143 6.282 6.539 ;
     RECT  15.915 6.317 16.29 6.539 ;
     RECT  17.1 6.317 19.998 6.539 ;
     RECT  12.564 5.801 14.274 6.691 ;
     RECT  17.1 6.539 17.118 6.719 ;
     RECT  18.216 6.539 19.998 6.719 ;
     RECT  19.944 6.719 19.998 6.817 ;
     RECT  12.564 6.691 15.174 6.845 ;
     RECT  12.564 6.845 13.497 6.859 ;
     RECT  19.944 6.817 20.538 6.989 ;
     RECT  14.256 6.845 15.174 7.115 ;
     RECT  15.156 7.115 15.174 7.151 ;
     RECT  15.915 6.539 16.197 7.231 ;
     RECT  14.256 7.115 14.274 7.259 ;
     RECT  12.096 6.859 13.497 7.277 ;
     RECT  18.216 6.719 19.062 7.321 ;
     RECT  12.24 7.277 13.497 7.349 ;
     RECT  2.232 6.539 6.21 7.465 ;
     RECT  7.815 2.413 8.097 7.501 ;
     RECT  15.264 7.231 16.197 7.501 ;
     RECT  7.488 7.501 8.097 7.619 ;
     RECT  17.64 7.321 19.062 7.663 ;
     RECT  19.944 6.989 19.998 7.663 ;
     RECT  17.64 7.663 19.998 7.699 ;
     RECT  15.264 7.501 16.614 7.723 ;
     RECT  17.496 7.699 19.998 7.723 ;
     RECT  15.264 7.723 19.998 7.763 ;
     RECT  17.1 7.763 19.998 7.889 ;
     RECT  1.152 7.291 1.17 7.949 ;
     RECT  17.1 7.889 19.062 7.961 ;
     RECT  19.944 7.889 19.998 7.961 ;
     RECT  17.352 7.961 19.062 8.033 ;
     RECT  15.264 7.763 16.326 8.041 ;
     RECT  2.232 7.465 6.57 8.131 ;
     RECT  12.6 7.349 13.497 8.131 ;
     RECT  14.976 8.041 16.326 8.131 ;
     RECT  7.668 7.619 8.097 8.159 ;
     RECT  7.815 8.159 8.097 8.275 ;
     RECT  12.24 8.131 16.326 8.429 ;
     RECT  12.06 8.491 12.078 8.537 ;
     RECT  12.816 8.429 16.326 8.609 ;
     RECT  0.828 8.509 0.846 8.635 ;
     RECT  2.232 8.131 6.606 8.671 ;
     RECT  18.576 8.033 19.062 8.683 ;
     RECT  19.944 7.961 19.962 8.683 ;
     RECT  14.508 8.609 16.326 8.735 ;
     RECT  17.352 8.033 17.694 8.743 ;
     RECT  17.1 8.743 17.694 8.779 ;
     RECT  18.576 8.683 19.962 8.779 ;
     RECT  0.252 8.635 0.846 8.813 ;
     RECT  14.652 8.735 16.326 8.815 ;
     RECT  17.1 8.779 19.962 8.815 ;
     RECT  7.815 8.275 8.154 8.969 ;
     RECT  14.652 8.815 19.962 8.969 ;
     RECT  2.232 8.671 7.038 8.977 ;
     RECT  7.815 8.969 8.097 8.977 ;
     RECT  15.915 8.969 19.962 9.005 ;
     RECT  15.915 9.005 17.658 9.011 ;
     RECT  18.396 9.005 19.962 9.077 ;
     RECT  17.1 9.011 17.658 9.239 ;
     RECT  17.496 9.239 17.658 9.383 ;
     RECT  18.396 9.077 19.062 9.383 ;
     RECT  12.816 8.609 13.734 9.509 ;
     RECT  14.652 8.969 14.994 9.517 ;
     RECT  19.944 9.077 19.962 9.625 ;
     RECT  14.508 9.517 14.994 9.661 ;
     RECT  18.504 9.383 19.062 9.689 ;
     RECT  0.828 8.813 0.846 9.691 ;
     RECT  19.944 9.625 20.538 9.773 ;
     RECT  12.816 9.509 13.497 9.925 ;
     RECT  14.256 9.661 14.994 9.931 ;
     RECT  14.256 9.931 15.174 9.959 ;
     RECT  12.096 9.925 13.497 9.965 ;
     RECT  0.252 9.691 0.846 10.027 ;
     RECT  18.615 9.689 19.062 10.129 ;
     RECT  0.216 10.027 0.846 10.157 ;
     RECT  17.496 9.383 17.514 10.165 ;
     RECT  18.615 10.129 19.098 10.319 ;
     RECT  15.915 9.011 16.254 10.327 ;
     RECT  15.915 10.327 16.65 10.411 ;
     RECT  17.496 10.165 17.658 10.411 ;
     RECT  14.652 9.959 15.174 10.435 ;
     RECT  15.915 10.411 17.658 10.435 ;
     RECT  14.652 10.435 17.658 10.471 ;
     RECT  18.615 10.319 19.062 10.471 ;
     RECT  14.652 10.471 19.062 10.589 ;
     RECT  17.496 10.589 19.062 10.661 ;
     RECT  14.652 10.589 16.65 10.939 ;
     RECT  14.58 10.939 16.65 11.011 ;
     RECT  0.288 10.157 0.846 11.035 ;
     RECT  12.24 9.965 13.497 11.129 ;
     RECT  12.888 11.129 13.497 11.179 ;
     RECT  18.252 10.661 19.062 11.209 ;
     RECT  12.06 11.209 12.078 11.261 ;
     RECT  12.888 11.179 13.698 11.281 ;
     RECT  14.544 11.011 16.65 11.281 ;
     RECT  12.888 11.281 16.65 11.371 ;
     RECT  17.496 10.661 17.514 11.371 ;
     RECT  12.888 11.371 17.514 11.399 ;
     RECT  18.252 11.209 19.098 11.399 ;
     RECT  12.888 11.399 13.698 11.435 ;
     RECT  15.336 11.399 17.514 11.515 ;
     RECT  18.252 11.399 19.062 11.515 ;
     RECT  2.232 8.977 8.097 11.551 ;
     RECT  2.232 11.551 8.802 11.669 ;
     RECT  0.216 11.035 0.846 11.693 ;
     RECT  2.232 11.669 8.097 11.713 ;
     RECT  15.336 11.515 19.062 11.849 ;
     RECT  2.016 11.713 8.097 11.933 ;
     RECT  15.336 11.849 17.694 11.975 ;
     RECT  12.96 11.435 13.698 12.181 ;
     RECT  12.708 12.181 13.698 12.283 ;
     RECT  14.58 11.399 14.598 12.325 ;
     RECT  14.508 12.325 14.598 12.361 ;
     RECT  15.336 11.975 17.514 12.361 ;
     RECT  18.432 11.849 19.062 12.361 ;
     RECT  12.384 12.283 13.698 12.451 ;
     RECT  14.508 12.361 17.514 12.451 ;
     RECT  12.384 12.451 17.514 12.551 ;
     RECT  10.515 4.145 10.797 12.631 ;
     RECT  10.515 12.631 11.214 12.749 ;
     RECT  14.292 12.551 17.514 12.749 ;
     RECT  2.232 11.933 8.097 12.763 ;
     RECT  12.384 12.551 13.497 12.829 ;
     RECT  12.06 12.829 13.497 12.893 ;
     RECT  0.828 11.693 0.846 12.901 ;
     RECT  1.728 12.763 8.097 12.901 ;
     RECT  8.856 12.829 8.874 12.901 ;
     RECT  14.58 12.749 17.514 12.901 ;
     RECT  18.432 12.361 19.098 12.901 ;
     RECT  1.728 12.901 8.874 13.019 ;
     RECT  10.515 12.749 10.854 13.019 ;
     RECT  12.24 12.893 13.497 13.091 ;
     RECT  14.58 12.901 19.098 13.135 ;
     RECT  19.944 9.773 19.998 13.135 ;
     RECT  0.828 12.901 0.882 13.339 ;
     RECT  14.58 13.135 19.998 13.559 ;
     RECT  15.915 13.559 19.098 13.595 ;
     RECT  14.58 13.559 14.994 13.639 ;
     RECT  1.728 13.019 8.097 13.739 ;
     RECT  12.96 13.091 13.497 13.837 ;
     RECT  0.252 13.339 0.882 13.867 ;
     RECT  12.888 13.837 13.497 13.909 ;
     RECT  12.06 13.909 12.078 13.949 ;
     RECT  12.888 13.909 13.698 13.981 ;
     RECT  14.544 13.639 14.994 13.981 ;
     RECT  12.24 13.981 14.994 14.099 ;
     RECT  0.252 13.867 1.17 14.141 ;
     RECT  14.58 14.099 14.994 14.207 ;
     RECT  19.944 13.559 19.998 14.242 ;
     RECT  12.24 14.099 13.497 14.243 ;
     RECT  19.944 14.242 20.034 14.441 ;
     RECT  14.652 14.207 14.994 14.449 ;
     RECT  15.915 13.595 19.062 14.449 ;
     RECT  14.652 14.449 19.062 14.521 ;
     RECT  14.652 14.521 19.098 14.813 ;
     RECT  0.252 14.141 0.882 14.827 ;
     RECT  12.96 14.243 13.497 14.827 ;
     RECT  17.28 14.813 19.098 14.909 ;
     RECT  18.18 14.909 19.098 14.945 ;
     RECT  0.216 14.827 0.882 14.957 ;
     RECT  18.18 14.945 18.954 14.981 ;
     RECT  14.652 14.813 16.29 14.989 ;
     RECT  18.216 14.981 18.954 15.053 ;
     RECT  0.828 14.957 0.882 15.061 ;
     RECT  12.96 14.827 13.734 15.151 ;
     RECT  14.544 14.989 16.29 15.151 ;
     RECT  0.828 15.061 0.918 15.163 ;
     RECT  0.828 15.163 1.17 15.307 ;
     RECT  12.96 15.151 16.29 15.449 ;
     RECT  12.96 15.449 13.734 15.457 ;
     RECT  19.944 14.441 19.998 15.521 ;
     RECT  12.06 15.403 12.078 15.601 ;
     RECT  12.888 15.457 13.734 15.601 ;
     RECT  0.828 15.307 1.242 15.691 ;
     RECT  0.216 15.691 1.242 15.821 ;
     RECT  18.615 15.053 18.954 15.835 ;
     RECT  17.424 14.909 17.442 15.871 ;
     RECT  18.615 15.835 19.062 15.871 ;
     RECT  12.06 15.601 13.734 15.899 ;
     RECT  14.652 15.449 16.29 15.979 ;
     RECT  17.424 15.871 19.062 15.979 ;
     RECT  19.944 15.521 19.962 15.979 ;
     RECT  0.828 15.821 1.242 16.069 ;
     RECT  2.052 13.739 8.097 16.069 ;
     RECT  12.96 15.899 13.734 16.231 ;
     RECT  14.652 15.979 19.962 16.231 ;
     RECT  12.96 16.231 19.962 16.259 ;
     RECT  0.828 16.069 8.097 16.267 ;
     RECT  15.915 16.259 19.962 16.315 ;
     RECT  15.915 16.315 19.998 16.403 ;
     RECT  17.208 16.403 19.998 16.439 ;
     RECT  17.208 16.439 17.658 16.529 ;
     RECT  18.615 16.439 19.998 16.529 ;
     RECT  12.06 15.899 12.078 16.681 ;
     RECT  12.96 16.259 15.174 16.681 ;
     RECT  0.828 16.267 8.298 16.699 ;
     RECT  12.06 16.681 15.174 16.799 ;
     RECT  0.216 16.699 8.298 16.829 ;
     RECT  12.06 16.799 12.078 16.871 ;
     RECT  19.944 16.529 19.998 16.871 ;
     RECT  12.924 16.799 15.174 16.907 ;
     RECT  12.924 16.907 13.59 17.069 ;
     RECT  12.924 17.069 13.497 17.105 ;
     RECT  17.424 16.529 17.658 17.185 ;
     RECT  18.615 16.529 19.062 17.185 ;
     RECT  15.915 16.403 16.29 17.221 ;
     RECT  19.98 16.871 19.998 17.323 ;
     RECT  17.424 17.185 19.062 17.419 ;
     RECT  15.915 17.221 16.614 17.455 ;
     RECT  17.424 17.419 19.242 17.455 ;
     RECT  14.652 16.907 15.174 17.491 ;
     RECT  15.915 17.455 19.242 17.491 ;
     RECT  19.98 17.323 20.034 17.681 ;
     RECT  14.652 17.491 19.242 17.707 ;
     RECT  19.98 17.681 19.998 17.707 ;
     RECT  14.652 17.707 19.998 17.879 ;
     RECT  12.96 17.105 13.497 17.959 ;
     RECT  14.652 17.879 19.17 17.995 ;
     RECT  12.24 17.959 13.698 18.031 ;
     RECT  14.508 17.995 19.17 18.031 ;
     RECT  0.252 16.829 8.298 18.091 ;
     RECT  0.216 18.091 8.298 18.149 ;
     RECT  12.24 18.031 19.17 18.149 ;
     RECT  19.944 17.879 19.998 18.221 ;
     RECT  12.06 18.187 12.078 18.227 ;
     RECT  14.508 18.149 19.17 18.293 ;
     RECT  12.888 18.149 13.698 18.419 ;
     RECT  12.888 18.419 13.497 18.455 ;
     RECT  10.515 13.019 10.797 18.535 ;
     RECT  10.515 18.535 10.854 18.761 ;
     RECT  14.652 18.293 19.17 18.797 ;
     RECT  17.1 18.797 19.17 18.805 ;
     RECT  19.944 18.221 19.962 18.805 ;
     RECT  17.1 18.805 19.962 19.139 ;
     RECT  0.792 18.149 8.298 19.345 ;
     RECT  14.652 18.797 14.67 19.345 ;
     RECT  0.18 19.345 8.298 19.381 ;
     RECT  0.18 19.381 8.73 19.499 ;
     RECT  13.032 18.455 13.497 19.531 ;
     RECT  12.06 19.531 12.078 19.571 ;
     RECT  13.032 19.531 13.698 19.615 ;
     RECT  14.508 19.345 14.67 19.643 ;
     RECT  12.924 19.615 13.698 19.651 ;
     RECT  14.652 19.643 14.67 19.651 ;
     RECT  15.915 18.797 16.29 19.651 ;
     RECT  10.515 18.761 10.797 19.741 ;
     RECT  12.24 19.651 13.878 19.769 ;
     RECT  0.18 19.499 8.298 19.813 ;
     RECT  10.515 19.741 10.854 19.877 ;
     RECT  17.424 19.139 19.962 19.921 ;
     RECT  17.1 19.921 19.962 20.039 ;
     RECT  14.652 19.651 16.29 20.047 ;
     RECT  17.1 20.039 19.098 20.047 ;
     RECT  0.072 19.813 8.298 20.119 ;
     RECT  14.652 20.047 19.098 20.345 ;
     RECT  14.652 20.345 16.65 20.417 ;
     RECT  13.032 19.769 13.497 20.659 ;
     RECT  14.652 20.417 16.29 20.731 ;
     RECT  13.032 20.659 13.698 20.779 ;
     RECT  12.24 19.769 12.258 20.827 ;
     RECT  12.06 20.827 12.258 20.849 ;
     RECT  13.032 20.779 13.734 20.857 ;
     RECT  12.06 20.849 12.078 20.885 ;
     RECT  12.888 20.857 13.734 21.001 ;
     RECT  14.544 20.731 16.29 21.001 ;
     RECT  12.888 21.001 16.29 21.119 ;
     RECT  12.888 21.119 13.698 21.227 ;
     RECT  14.652 21.119 16.29 21.235 ;
     RECT  14.652 21.235 16.614 21.355 ;
     RECT  17.424 20.345 19.098 21.355 ;
     RECT  14.652 21.355 19.098 21.541 ;
     RECT  19.944 20.039 19.962 21.541 ;
     RECT  12.888 21.227 13.497 21.643 ;
     RECT  14.652 21.541 19.962 21.659 ;
     RECT  19.944 21.659 19.962 21.835 ;
     RECT  10.515 19.877 10.797 21.973 ;
     RECT  12.06 21.643 13.497 21.973 ;
     RECT  10.515 21.973 13.497 22.009 ;
     RECT  10.515 22.009 13.806 22.045 ;
     RECT  14.652 21.659 19.098 22.045 ;
     RECT  10.515 22.045 19.098 22.199 ;
     RECT  12.924 22.199 19.098 22.469 ;
     RECT  10.515 22.199 12.078 22.649 ;
     RECT  19.944 21.835 19.998 22.811 ;
     RECT  13.032 22.469 19.098 23.279 ;
     RECT  15.915 23.279 19.098 23.315 ;
     RECT  13.032 23.279 14.994 23.549 ;
     RECT  13.032 23.549 14.742 23.557 ;
     RECT  12.06 22.649 12.078 23.693 ;
     RECT  12.888 23.557 14.742 23.701 ;
     RECT  12.24 23.701 14.742 23.819 ;
     RECT  12.24 23.819 13.497 23.855 ;
     RECT  12.24 23.855 12.258 23.927 ;
     RECT  17.424 23.315 19.098 23.935 ;
     RECT  19.944 22.811 19.962 23.935 ;
     RECT  14.508 23.819 14.742 23.936 ;
     RECT  17.424 23.935 19.962 24.089 ;
     RECT  15.915 23.315 16.29 24.169 ;
     RECT  17.424 24.089 19.098 24.169 ;
     RECT  15.48 24.169 16.29 24.241 ;
     RECT  17.172 24.169 19.098 24.241 ;
     RECT  15.48 24.241 19.098 24.359 ;
     RECT  14.652 23.936 14.742 24.367 ;
     RECT  15.48 24.359 17.694 24.367 ;
     RECT  14.652 24.367 17.694 24.503 ;
     RECT  14.652 24.503 17.658 24.509 ;
     RECT  17.172 24.509 17.658 24.629 ;
     RECT  17.316 24.629 17.658 24.665 ;
     RECT  13.032 23.855 13.497 24.709 ;
     RECT  14.652 24.509 14.994 24.709 ;
     RECT  19.944 24.089 19.962 24.709 ;
     RECT  12.24 24.709 12.258 24.899 ;
     RECT  13.032 24.709 14.994 24.899 ;
     RECT  19.944 24.709 19.998 24.989 ;
     RECT  13.032 24.899 14.67 25.015 ;
     RECT  12.096 25.045 12.114 25.085 ;
     RECT  0.036 20.119 8.298 25.124 ;
     RECT  12.924 25.015 14.67 25.169 ;
     RECT  13.032 25.169 13.914 25.205 ;
     RECT  17.424 24.665 17.658 25.249 ;
     RECT  18.615 24.359 19.098 25.249 ;
     RECT  17.424 25.249 19.098 25.321 ;
     RECT  17.424 25.321 19.206 25.555 ;
     RECT  19.944 24.989 19.962 25.555 ;
     RECT  14.652 25.169 14.67 25.675 ;
     RECT  15.915 24.509 16.29 25.675 ;
     RECT  17.424 25.555 19.962 25.675 ;
     RECT  14.652 25.675 19.962 25.709 ;
     RECT  9.036 25.789 9.054 25.979 ;
     RECT  13.032 25.205 13.497 25.987 ;
     RECT  14.652 25.709 19.206 26.015 ;
     RECT  9.324 25.987 9.342 26.087 ;
     RECT  14.652 26.015 17.442 26.131 ;
     RECT  14.544 26.131 17.442 26.285 ;
     RECT  13.032 25.987 13.554 26.329 ;
     RECT  13.032 26.329 13.698 26.401 ;
     RECT  13.032 26.401 13.878 26.519 ;
     RECT  13.032 26.519 13.554 26.627 ;
     RECT  13.032 26.627 13.497 26.635 ;
     RECT  12.924 26.635 13.497 26.671 ;
     RECT  19.944 25.709 19.962 26.683 ;
     RECT  14.652 26.285 17.442 26.761 ;
     RECT  18.252 26.015 19.098 26.761 ;
     RECT  12.096 26.671 13.497 26.789 ;
     RECT  12.924 26.789 13.497 26.825 ;
     RECT  19.944 26.683 19.998 26.861 ;
     RECT  0.072 25.124 8.298 26.905 ;
     RECT  0.072 26.905 8.37 27.031 ;
     RECT  0.072 27.031 8.442 27.131 ;
     RECT  14.652 26.761 19.098 27.139 ;
     RECT  19.944 26.861 19.962 27.139 ;
     RECT  14.652 27.139 19.962 27.329 ;
     RECT  13.032 26.825 13.497 27.355 ;
     RECT  17.424 27.329 19.098 27.473 ;
     RECT  14.652 27.329 16.362 27.599 ;
     RECT  15.444 27.599 16.362 27.671 ;
     RECT  12.096 26.789 12.114 27.715 ;
     RECT  14.652 27.599 14.67 27.715 ;
     RECT  13.032 27.355 13.698 27.751 ;
     RECT  14.544 27.715 14.67 27.751 ;
     RECT  19.908 27.329 19.962 27.773 ;
     RECT  0.072 27.131 8.406 27.869 ;
     RECT  12.096 27.715 12.258 27.869 ;
     RECT  13.032 27.751 14.67 27.869 ;
     RECT  13.032 27.869 13.698 27.877 ;
     RECT  15.444 27.671 16.29 27.941 ;
     RECT  12.888 27.877 13.698 28.139 ;
     RECT  12.888 28.139 13.497 28.175 ;
     RECT  18.396 27.473 19.098 28.291 ;
     RECT  14.508 27.869 14.67 28.493 ;
     RECT  17.424 27.473 17.442 28.525 ;
     RECT  18.396 28.291 19.17 28.525 ;
     RECT  19.944 27.773 19.962 28.525 ;
     RECT  17.424 28.525 17.658 28.561 ;
     RECT  18.396 28.525 19.962 28.561 ;
     RECT  15.624 27.941 16.29 28.759 ;
     RECT  17.424 28.561 19.962 28.759 ;
     RECT  0.072 27.869 8.298 28.831 ;
     RECT  15.48 28.759 19.962 28.985 ;
     RECT  14.652 28.493 14.67 29.029 ;
     RECT  15.48 28.985 19.242 29.029 ;
     RECT  14.652 29.029 19.242 29.057 ;
     RECT  0.072 28.831 8.586 29.129 ;
     RECT  14.652 29.057 17.694 29.371 ;
     RECT  12.24 29.227 12.258 29.489 ;
     RECT  13.032 28.175 13.497 29.497 ;
     RECT  12.888 29.497 13.497 29.569 ;
     RECT  12.888 29.569 13.698 29.641 ;
     RECT  14.544 29.371 17.694 29.641 ;
     RECT  12.06 29.569 12.078 29.645 ;
     RECT  12.888 29.641 17.694 29.645 ;
     RECT  14.292 29.645 17.694 29.759 ;
     RECT  12.888 29.645 13.497 29.795 ;
     RECT  18.615 29.057 19.242 29.803 ;
     RECT  18.615 29.803 19.962 29.839 ;
     RECT  14.652 29.759 17.694 29.911 ;
     RECT  18.504 29.839 19.962 29.911 ;
     RECT  14.652 29.911 19.962 30.029 ;
     RECT  14.652 30.029 17.694 30.065 ;
     RECT  14.652 30.065 17.442 30.299 ;
     RECT  18.576 30.029 19.962 30.523 ;
     RECT  18.576 30.523 19.998 30.569 ;
     RECT  14.652 30.299 16.614 30.641 ;
     RECT  14.652 30.641 16.29 30.685 ;
     RECT  0.072 29.129 8.298 30.749 ;
     RECT  14.508 30.685 16.29 30.749 ;
     RECT  18.576 30.569 19.098 30.919 ;
     RECT  13.032 29.795 13.497 30.955 ;
     RECT  18.396 30.919 19.098 30.955 ;
     RECT  12.924 30.955 13.497 30.991 ;
     RECT  14.508 30.749 15.066 30.991 ;
     RECT  17.424 30.299 17.442 30.991 ;
     RECT  18.288 30.955 19.098 30.991 ;
     RECT  12.096 30.991 15.066 31.037 ;
     RECT  12.24 31.037 15.066 31.109 ;
     RECT  19.944 30.569 19.998 31.253 ;
     RECT  13.032 31.109 15.066 31.289 ;
     RECT  15.915 30.749 16.29 31.483 ;
     RECT  17.424 30.991 19.098 31.483 ;
     RECT  15.915 31.483 19.098 31.579 ;
     RECT  15.336 31.579 19.098 31.765 ;
     RECT  19.944 31.253 19.962 31.765 ;
     RECT  15.336 31.765 19.962 31.919 ;
     RECT  15.336 31.919 16.362 31.949 ;
     RECT  14.58 31.289 14.598 32.035 ;
     RECT  17.424 31.919 19.098 32.063 ;
     RECT  14.544 32.035 14.598 32.071 ;
     RECT  15.336 31.949 16.197 32.071 ;
     RECT  19.944 31.919 19.962 32.251 ;
     RECT  13.032 31.289 13.497 32.269 ;
     RECT  12.24 31.109 12.258 32.305 ;
     RECT  13.032 32.269 13.698 32.305 ;
     RECT  12.24 32.305 13.698 32.341 ;
     RECT  14.544 32.071 16.197 32.341 ;
     RECT  19.944 32.251 19.998 32.369 ;
     RECT  12.24 32.341 16.197 32.459 ;
     RECT  12.888 32.459 13.497 32.603 ;
     RECT  14.58 32.459 16.197 32.737 ;
     RECT  18.324 32.063 19.098 32.737 ;
     RECT  17.424 32.063 17.442 32.845 ;
     RECT  18.324 32.737 19.17 32.845 ;
     RECT  14.58 32.737 16.578 32.971 ;
     RECT  17.424 32.845 19.17 32.971 ;
     RECT  0.072 30.749 8.262 33.043 ;
     RECT  14.58 32.971 19.17 33.115 ;
     RECT  19.944 32.369 19.962 33.115 ;
     RECT  14.58 33.115 19.962 33.269 ;
     RECT  17.424 33.269 19.962 33.307 ;
     RECT  17.424 33.307 19.998 33.341 ;
     RECT  14.58 33.269 16.686 33.349 ;
     RECT  18.324 33.341 19.998 33.377 ;
     RECT  18.324 33.377 19.962 33.449 ;
     RECT  14.544 33.349 16.686 33.511 ;
     RECT  14.256 33.511 16.686 33.539 ;
     RECT  13.032 32.603 13.497 33.583 ;
     RECT  14.256 33.539 15.174 33.583 ;
     RECT  13.032 33.583 15.174 33.629 ;
     RECT  14.256 33.629 15.174 33.809 ;
     RECT  13.032 33.629 13.497 33.817 ;
     RECT  12.06 32.491 12.078 33.961 ;
     RECT  12.888 33.817 13.497 33.961 ;
     RECT  12.06 33.961 13.497 34.079 ;
     RECT  17.424 33.341 17.442 34.087 ;
     RECT  12.888 34.079 13.497 34.115 ;
     RECT  17.424 34.087 17.658 34.195 ;
     RECT  18.615 33.449 19.962 34.195 ;
     RECT  14.58 33.809 15.174 34.315 ;
     RECT  15.915 33.539 16.686 34.315 ;
     RECT  17.424 34.195 19.962 34.315 ;
     RECT  14.58 34.315 19.998 34.385 ;
     RECT  14.58 34.385 17.442 34.591 ;
     RECT  18.288 34.385 19.998 34.619 ;
     RECT  18.36 34.619 19.098 34.763 ;
     RECT  19.944 34.619 19.998 34.763 ;
     RECT  13.032 34.115 13.497 34.795 ;
     RECT  14.256 34.591 17.442 34.795 ;
     RECT  13.032 34.795 17.442 34.897 ;
     RECT  12.06 34.079 12.078 35.041 ;
     RECT  12.924 34.897 17.442 35.041 ;
     RECT  12.06 35.041 17.442 35.303 ;
     RECT  12.348 35.303 17.442 35.429 ;
     RECT  0.036 33.043 8.262 35.453 ;
     RECT  14.652 35.429 17.442 35.473 ;
     RECT  12.348 35.429 13.662 35.501 ;
     RECT  14.652 35.473 17.514 35.545 ;
     RECT  14.652 35.545 17.694 35.581 ;
     RECT  18.615 34.763 19.098 35.581 ;
     RECT  0.108 35.453 8.262 35.609 ;
     RECT  12.348 35.501 13.497 35.699 ;
     RECT  19.944 34.763 19.962 35.707 ;
     RECT  14.652 35.581 19.098 35.815 ;
     RECT  19.944 35.707 19.998 35.815 ;
     RECT  12.636 35.699 13.497 35.885 ;
     RECT  14.652 35.815 19.998 35.885 ;
     RECT  17.352 35.885 19.998 35.969 ;
     RECT  18.18 35.969 19.998 36.113 ;
     RECT  0.18 35.609 8.262 36.125 ;
     RECT  17.352 35.969 17.442 36.149 ;
     RECT  14.652 35.885 16.254 36.211 ;
     RECT  18.615 36.113 19.998 36.239 ;
     RECT  12.888 35.885 13.497 36.391 ;
     RECT  14.256 36.211 16.254 36.391 ;
     RECT  12.888 36.391 16.254 36.461 ;
     RECT  0.216 36.125 8.262 36.557 ;
     RECT  12.096 36.475 12.114 36.661 ;
     RECT  12.888 36.461 13.497 36.661 ;
     RECT  14.256 36.461 16.254 36.689 ;
     RECT  0.504 36.557 8.262 36.749 ;
     RECT  12.096 36.661 13.497 36.779 ;
     RECT  17.424 36.149 17.442 36.787 ;
     RECT  12.888 36.779 13.497 36.815 ;
     RECT  17.424 36.787 17.658 36.895 ;
     RECT  17.388 36.895 17.658 36.931 ;
     RECT  18.615 36.239 19.098 36.931 ;
     RECT  14.652 36.689 16.254 37.049 ;
     RECT  15.915 37.049 16.254 37.051 ;
     RECT  17.388 36.931 19.098 37.051 ;
     RECT  0.864 36.749 8.262 37.085 ;
     RECT  15.915 37.051 19.098 37.085 ;
     RECT  18.216 37.085 19.098 37.165 ;
     RECT  19.944 36.239 19.998 37.165 ;
     RECT  1.08 37.085 8.262 37.355 ;
     RECT  18.216 37.165 19.998 37.391 ;
     RECT  15.915 37.085 17.442 37.463 ;
     RECT  1.08 37.355 8.226 37.499 ;
     RECT  17.244 37.463 17.442 37.499 ;
     RECT  13.032 36.815 13.497 37.561 ;
     RECT  13.032 37.561 13.734 37.597 ;
     RECT  14.652 37.049 15.174 37.597 ;
     RECT  13.032 37.597 15.174 37.613 ;
     RECT  13.032 37.613 13.497 37.975 ;
     RECT  12.096 36.779 12.114 38.011 ;
     RECT  12.924 37.975 13.497 38.011 ;
     RECT  14.256 37.613 15.174 38.011 ;
     RECT  15.915 37.463 16.254 38.011 ;
     RECT  14.256 38.011 16.254 38.039 ;
     RECT  12.096 38.011 13.497 38.129 ;
     RECT  12.096 38.129 12.258 38.201 ;
     RECT  17.424 37.499 17.442 38.245 ;
     RECT  18.216 37.391 19.962 38.245 ;
     RECT  14.652 38.039 16.254 38.491 ;
     RECT  17.316 38.245 19.962 38.491 ;
     RECT  14.652 38.491 19.998 38.543 ;
     RECT  1.404 37.499 8.226 38.741 ;
     RECT  13.032 38.129 13.497 38.779 ;
     RECT  0.252 37.963 0.27 38.923 ;
     RECT  12.096 38.201 12.114 38.983 ;
     RECT  14.652 38.543 17.442 39.055 ;
     RECT  0.216 38.923 0.27 39.067 ;
     RECT  0.216 39.067 0.306 39.149 ;
     RECT  12.096 38.983 12.258 39.209 ;
     RECT  13.032 38.779 13.734 39.209 ;
     RECT  13.032 39.209 13.497 39.217 ;
     RECT  14.544 39.055 17.442 39.361 ;
     RECT  1.404 38.741 8.154 39.479 ;
     RECT  14.256 39.361 17.442 39.479 ;
     RECT  18.216 38.543 19.998 39.479 ;
     RECT  14.652 39.479 17.442 39.487 ;
     RECT  18.216 39.479 19.098 39.487 ;
     RECT  12.888 39.217 13.497 39.515 ;
     RECT  14.652 39.487 19.098 39.551 ;
     RECT  0.252 39.149 0.306 39.629 ;
     RECT  14.652 39.551 19.062 39.785 ;
     RECT  19.944 39.479 19.998 39.865 ;
     RECT  19.944 39.865 20.538 39.917 ;
     RECT  14.652 39.785 17.442 40.019 ;
     RECT  17.1 40.019 17.442 40.055 ;
     RECT  17.316 40.055 17.442 40.325 ;
     RECT  14.652 40.019 16.29 40.405 ;
     RECT  0.324 39.643 0.342 40.441 ;
     RECT  0.324 40.441 0.558 40.459 ;
     RECT  0.216 40.459 0.558 40.589 ;
     RECT  18.396 39.785 19.062 40.603 ;
     RECT  13.032 39.515 13.497 40.675 ;
     RECT  14.508 40.405 16.29 40.703 ;
     RECT  12.924 40.675 13.497 40.711 ;
     RECT  12.096 40.711 13.878 40.781 ;
     RECT  12.24 40.781 13.878 40.829 ;
     RECT  17.424 40.325 17.442 40.945 ;
     RECT  18.396 40.603 19.098 40.945 ;
     RECT  19.944 39.917 19.998 40.945 ;
     RECT  0.252 40.589 0.558 41.021 ;
     RECT  9.18 40.801 9.198 41.179 ;
     RECT  14.652 40.703 16.29 41.179 ;
     RECT  17.424 40.945 19.098 41.179 ;
     RECT  9.18 41.179 9.234 41.251 ;
     RECT  9.144 41.251 9.234 41.279 ;
     RECT  19.944 40.945 20.538 41.309 ;
     RECT  14.652 41.179 19.098 41.369 ;
     RECT  1.908 39.479 8.154 41.405 ;
     RECT  14.652 41.369 16.65 41.441 ;
     RECT  14.652 41.441 16.29 41.501 ;
     RECT  0.288 41.021 0.558 41.549 ;
     RECT  9.144 41.279 9.162 41.549 ;
     RECT  15.876 41.501 16.29 41.639 ;
     RECT  17.424 41.369 19.098 41.675 ;
     RECT  14.652 41.501 15.066 41.791 ;
     RECT  12.24 40.829 12.258 41.851 ;
     RECT  12.096 41.851 12.258 41.909 ;
     RECT  13.032 40.829 13.734 41.917 ;
     RECT  14.544 41.791 15.066 41.945 ;
     RECT  0.504 41.549 0.558 41.947 ;
     RECT  12.888 41.917 13.734 42.061 ;
     RECT  0.504 41.947 1.17 42.077 ;
     RECT  17.424 41.675 19.062 42.151 ;
     RECT  12.888 42.061 13.878 42.179 ;
     RECT  12.888 42.179 13.734 42.215 ;
     RECT  19.944 41.309 19.998 42.283 ;
     RECT  15.915 41.639 16.29 42.427 ;
     RECT  17.1 42.151 19.062 42.427 ;
     RECT  19.944 42.283 20.034 42.521 ;
     RECT  14.652 41.945 15.066 42.565 ;
     RECT  15.915 42.427 19.062 42.565 ;
     RECT  14.652 42.565 19.062 42.601 ;
     RECT  14.652 42.601 19.098 42.719 ;
     RECT  17.1 42.719 19.098 42.755 ;
     RECT  0.504 42.077 0.558 42.961 ;
     RECT  1.908 41.405 8.097 42.961 ;
     RECT  17.424 42.755 19.098 43.025 ;
     RECT  0.468 42.961 8.097 43.105 ;
     RECT  14.652 42.719 16.29 43.105 ;
     RECT  13.032 42.215 13.734 43.231 ;
     RECT  14.508 43.105 16.29 43.231 ;
     RECT  0.468 43.105 8.154 43.259 ;
     RECT  13.032 43.231 16.29 43.331 ;
     RECT  12.096 43.483 12.114 43.529 ;
     RECT  14.256 43.331 16.29 43.529 ;
     RECT  13.032 43.331 13.497 43.537 ;
     RECT  1.908 43.259 8.154 43.565 ;
     RECT  12.888 43.537 13.497 43.681 ;
     RECT  0.468 43.259 1.17 43.757 ;
     RECT  12.24 43.681 13.497 43.799 ;
     RECT  12.888 43.799 13.497 43.835 ;
     RECT  14.652 43.529 16.29 43.915 ;
     RECT  17.424 43.025 19.062 43.915 ;
     RECT  14.652 43.915 19.062 43.951 ;
     RECT  14.652 43.951 19.098 44.149 ;
     RECT  19.944 42.521 19.998 44.149 ;
     RECT  0.468 43.757 0.486 44.155 ;
     RECT  14.652 44.149 19.998 44.339 ;
     RECT  14.652 44.339 19.098 44.419 ;
     RECT  14.544 44.419 19.098 44.447 ;
     RECT  14.544 44.447 17.73 44.581 ;
     RECT  12.06 44.581 12.078 44.617 ;
     RECT  13.032 43.835 13.497 44.779 ;
     RECT  14.292 44.581 17.73 44.779 ;
     RECT  12.06 44.617 12.258 44.879 ;
     RECT  12.06 44.879 12.078 44.951 ;
     RECT  19.944 44.339 19.998 44.951 ;
     RECT  13.032 44.779 17.73 44.995 ;
     RECT  18.615 44.447 19.098 45.067 ;
     RECT  19.944 44.951 19.962 45.067 ;
     RECT  0.252 44.155 0.486 45.115 ;
     RECT  12.924 44.995 17.73 45.149 ;
     RECT  18.615 45.067 19.962 45.229 ;
     RECT  0.216 45.115 0.486 45.245 ;
     RECT  0.252 45.245 0.486 45.301 ;
     RECT  10.515 22.649 10.797 45.301 ;
     RECT  13.032 45.149 17.73 45.301 ;
     RECT  18.504 45.229 19.962 45.301 ;
     RECT  0.252 45.301 0.558 45.341 ;
     RECT  10.515 45.301 10.854 45.419 ;
     RECT  1.908 43.565 8.097 45.563 ;
     RECT  13.032 45.301 19.962 45.581 ;
     RECT  13.032 45.581 16.29 45.599 ;
     RECT  0.54 45.341 0.558 45.677 ;
     RECT  17.1 45.581 19.962 45.689 ;
     RECT  17.424 45.689 19.962 45.833 ;
     RECT  17.424 45.833 17.766 45.869 ;
     RECT  13.032 45.599 14.994 45.959 ;
     RECT  1.908 45.563 6.93 46.229 ;
     RECT  12.096 46.171 12.114 46.229 ;
     RECT  13.032 45.959 14.67 46.229 ;
     RECT  13.032 46.229 13.914 46.237 ;
     RECT  12.888 46.237 13.914 46.265 ;
     RECT  12.888 46.265 13.734 46.381 ;
     RECT  15.915 45.599 16.29 46.381 ;
     RECT  12.24 46.381 13.734 46.535 ;
     RECT  12.24 46.535 12.258 46.643 ;
     RECT  14.652 46.229 14.67 46.747 ;
     RECT  15.516 46.381 16.29 46.747 ;
     RECT  18.615 45.833 19.962 46.769 ;
     RECT  14.652 46.747 16.29 46.777 ;
     RECT  17.424 45.869 17.658 46.777 ;
     RECT  19.944 46.769 19.962 46.795 ;
     RECT  2.232 46.229 6.93 46.849 ;
     RECT  7.815 45.563 8.097 46.849 ;
     RECT  18.615 46.769 19.026 46.877 ;
     RECT  0.504 46.741 0.522 46.891 ;
     RECT  14.652 46.777 17.658 46.921 ;
     RECT  18.615 46.877 18.99 46.921 ;
     RECT  0.288 46.891 0.522 47.021 ;
     RECT  2.232 46.849 8.097 47.075 ;
     RECT  14.652 46.921 18.99 47.075 ;
     RECT  19.944 46.795 19.998 47.111 ;
     RECT  0.468 47.021 0.522 47.119 ;
     RECT  17.028 47.075 18.99 47.219 ;
     RECT  13.032 46.535 13.734 47.315 ;
     RECT  14.652 47.075 16.29 47.317 ;
     RECT  0.468 47.119 0.558 47.389 ;
     RECT  2.232 47.075 6.858 47.417 ;
     RECT  2.304 47.417 6.858 47.453 ;
     RECT  12.06 47.611 12.078 47.651 ;
     RECT  19.944 47.111 19.962 47.651 ;
     RECT  0.468 47.389 1.17 47.687 ;
     RECT  13.032 47.315 13.497 47.695 ;
     RECT  17.1 47.219 18.99 47.695 ;
     RECT  12.924 47.695 13.497 47.731 ;
     RECT  2.304 47.453 6.75 47.741 ;
     RECT  14.256 47.317 16.29 47.759 ;
     RECT  12.24 47.731 13.497 47.849 ;
     RECT  17.1 47.695 19.062 47.851 ;
     RECT  2.304 47.741 6.354 47.885 ;
     RECT  12.924 47.849 13.497 47.885 ;
     RECT  14.652 47.759 16.29 48.163 ;
     RECT  17.1 47.851 19.458 48.163 ;
     RECT  7.815 47.075 8.097 48.199 ;
     RECT  7.776 48.199 8.097 48.271 ;
     RECT  14.652 48.163 19.458 48.299 ;
     RECT  7.704 48.271 8.097 48.389 ;
     RECT  14.652 48.299 19.062 48.389 ;
     RECT  14.652 48.389 16.29 48.467 ;
     RECT  17.1 48.389 19.062 48.695 ;
     RECT  14.652 48.467 14.994 48.703 ;
     RECT  0.468 47.687 0.558 48.749 ;
     RECT  12.24 48.703 12.258 48.775 ;
     RECT  13.032 47.885 13.497 48.775 ;
     RECT  2.34 47.885 6.354 48.811 ;
     RECT  12.24 48.775 13.497 48.859 ;
     RECT  0.504 48.749 0.558 48.901 ;
     RECT  2.304 48.811 6.354 48.929 ;
     RECT  12.096 48.859 13.497 48.929 ;
     RECT  0.504 48.901 1.17 48.941 ;
     RECT  12.564 48.929 13.497 48.973 ;
     RECT  14.22 48.703 14.994 48.973 ;
     RECT  0.54 48.941 1.17 49.001 ;
     RECT  2.304 48.929 5.598 49.037 ;
     RECT  12.564 48.973 14.994 49.037 ;
     RECT  19.944 48.523 19.962 49.243 ;
     RECT  12.564 49.037 13.497 49.343 ;
     RECT  14.22 49.037 14.994 49.343 ;
     RECT  6.408 49.081 6.858 49.351 ;
     RECT  6.408 49.351 6.894 49.469 ;
     RECT  15.876 48.467 16.29 49.477 ;
     RECT  17.424 48.695 19.062 49.477 ;
     RECT  19.944 49.243 19.998 49.541 ;
     RECT  14.652 49.343 14.994 49.579 ;
     RECT  15.876 49.477 19.062 49.579 ;
     RECT  19.944 49.541 19.962 49.579 ;
     RECT  2.376 49.037 5.598 49.711 ;
     RECT  6.408 49.469 6.534 49.711 ;
     RECT  2.376 49.711 6.534 49.739 ;
     RECT  0.54 49.001 0.558 49.819 ;
     RECT  2.376 49.739 6.282 49.847 ;
     RECT  14.652 49.579 19.962 49.847 ;
     RECT  0.216 49.819 0.558 49.949 ;
     RECT  2.376 49.847 5.397 50.045 ;
     RECT  14.652 49.847 19.098 50.117 ;
     RECT  14.652 50.117 17.658 50.125 ;
     RECT  14.508 50.125 17.658 50.161 ;
     RECT  6.12 49.847 6.282 50.279 ;
     RECT  6.264 50.279 6.282 50.351 ;
     RECT  12.06 50.299 12.078 50.351 ;
     RECT  12.96 49.343 13.497 50.395 ;
     RECT  12.924 50.395 13.497 50.431 ;
     RECT  14.328 50.161 17.658 50.431 ;
     RECT  12.24 50.431 17.658 50.585 ;
     RECT  18.615 50.117 19.098 50.587 ;
     RECT  19.944 49.847 19.962 50.587 ;
     RECT  12.24 50.585 13.878 50.657 ;
     RECT  12.24 50.657 12.258 50.729 ;
     RECT  0.54 49.949 0.558 50.813 ;
     RECT  2.376 50.045 3.006 50.899 ;
     RECT  18.615 50.587 19.962 50.899 ;
     RECT  18.432 50.899 19.962 50.927 ;
     RECT  14.652 50.585 17.658 50.963 ;
     RECT  18.432 50.927 19.062 50.971 ;
     RECT  2.232 50.899 3.006 51.005 ;
     RECT  3.744 50.045 5.397 51.089 ;
     RECT  14.652 50.963 17.046 51.089 ;
     RECT  5.076 51.089 5.397 51.125 ;
     RECT  3.744 51.089 4.158 51.149 ;
     RECT  15.876 51.089 16.65 51.161 ;
     RECT  2.304 51.005 3.006 51.169 ;
     RECT  3.744 51.149 4.014 51.169 ;
     RECT  19.944 50.927 19.962 51.307 ;
     RECT  13.032 50.657 13.734 51.403 ;
     RECT  14.652 51.089 15.066 51.403 ;
     RECT  2.304 51.169 4.014 51.431 ;
     RECT  15.876 51.161 16.218 51.467 ;
     RECT  12.096 51.307 12.114 51.475 ;
     RECT  2.34 51.431 4.014 51.533 ;
     RECT  13.032 51.403 15.066 51.539 ;
     RECT  2.376 51.533 4.014 51.629 ;
     RECT  12.096 51.475 12.258 51.629 ;
     RECT  13.032 51.539 14.994 51.629 ;
     RECT  13.032 51.629 14.67 51.637 ;
     RECT  18.108 50.971 19.062 51.673 ;
     RECT  12.888 51.637 14.67 51.701 ;
     RECT  18.108 51.673 19.098 51.745 ;
     RECT  19.944 51.307 19.998 51.745 ;
     RECT  3.996 51.629 4.014 51.773 ;
     RECT  18.108 51.745 19.998 51.773 ;
     RECT  2.376 51.629 2.934 51.899 ;
     RECT  12.888 51.701 14.166 51.899 ;
     RECT  12.888 51.899 14.022 51.935 ;
     RECT  18.615 51.773 19.998 51.971 ;
     RECT  15.876 51.467 16.197 52.043 ;
     RECT  2.376 51.899 2.79 52.169 ;
     RECT  9.684 51.439 9.702 52.169 ;
     RECT  18.615 51.971 19.242 52.169 ;
     RECT  6.804 52.141 6.822 52.241 ;
     RECT  19.98 51.971 19.998 52.241 ;
     RECT  2.376 52.169 2.697 52.349 ;
     RECT  2.415 52.349 2.697 53.747 ;
     RECT  5.115 51.125 5.397 53.747 ;
     RECT  7.815 48.389 8.097 53.747 ;
     RECT  10.515 45.419 10.797 53.747 ;
     RECT  13.215 51.935 13.497 53.747 ;
     RECT  15.915 52.043 16.197 53.747 ;
     RECT  18.615 52.169 18.897 53.747 ;
     RECT  2.415 53.747 2.505 54.017 ;
     RECT  5.115 53.747 5.205 54.017 ;
     RECT  7.815 53.747 7.905 54.017 ;
     RECT  10.515 53.747 10.605 54.017 ;
     RECT  13.215 53.747 13.305 54.017 ;
     RECT  15.915 53.747 16.005 54.017 ;
     RECT  18.615 53.747 18.705 54.017 ;
    LAYER M4 ;
     RECT  0.061 34.224 0.133 34.248 ;
     RECT  0.025 35.424 0.133 35.448 ;
     RECT  0.133 33.696 0.156 35.448 ;
     RECT  0.156 4.512 0.965 51.672 ;
     RECT  0.965 4.512 1.217 35.88 ;
     RECT  1.217 4.512 2.408 35.016 ;
     RECT  0.965 36.864 2.408 51.672 ;
     RECT  2.408 2.148 2.512 54.012 ;
     RECT  2.512 2.418 2.704 53.742 ;
     RECT  2.704 20.208 2.819 31.656 ;
     RECT  2.704 4.512 2.837 18.456 ;
     RECT  2.704 34.8 2.837 51.192 ;
     RECT  2.819 20.208 2.873 29.88 ;
     RECT  2.873 20.208 2.881 27.144 ;
     RECT  2.837 34.8 2.963 51.144 ;
     RECT  2.881 20.928 3.053 27.144 ;
     RECT  2.704 32.736 3.053 33.048 ;
     RECT  2.963 34.8 3.089 35.016 ;
     RECT  2.819 30.96 3.377 31.656 ;
     RECT  3.053 33.024 3.683 33.048 ;
     RECT  2.873 28.464 4.025 29.88 ;
     RECT  3.053 20.928 4.097 26.904 ;
     RECT  3.089 34.992 4.273 35.016 ;
     RECT  2.837 5.232 5.108 18.456 ;
     RECT  4.097 20.928 5.108 24.648 ;
     RECT  4.097 26.016 5.108 26.904 ;
     RECT  4.025 28.464 5.108 28.488 ;
     RECT  4.025 29.76 5.108 29.88 ;
     RECT  3.377 30.96 5.108 30.984 ;
     RECT  4.273 34.752 5.108 35.016 ;
     RECT  2.963 37.2 5.108 51.144 ;
     RECT  5.108 2.148 5.212 54.012 ;
     RECT  5.212 2.418 5.404 53.742 ;
     RECT  5.404 20.928 5.465 24.12 ;
     RECT  5.404 29.76 5.501 29.88 ;
     RECT  5.404 6.048 5.645 6.072 ;
     RECT  5.404 14.112 5.645 18.456 ;
     RECT  5.404 46.896 5.645 47.736 ;
     RECT  5.404 8.064 5.717 10.68 ;
     RECT  5.501 29.76 5.717 29.784 ;
     RECT  5.645 14.112 5.753 16.392 ;
     RECT  5.404 38.448 5.933 43.416 ;
     RECT  5.933 38.448 5.969 41.976 ;
     RECT  5.717 8.064 6.005 9.288 ;
     RECT  5.969 38.448 6.005 41.448 ;
     RECT  5.404 12.48 6.077 12.504 ;
     RECT  5.753 14.112 6.077 15.768 ;
     RECT  5.465 20.928 6.131 23.352 ;
     RECT  6.131 20.928 6.185 22.536 ;
     RECT  5.404 34.8 6.257 34.824 ;
     RECT  6.005 38.448 6.257 41.4 ;
     RECT  6.185 20.928 6.293 22.488 ;
     RECT  6.077 14.688 6.401 15.768 ;
     RECT  6.293 21.696 6.545 22.488 ;
     RECT  6.401 15.744 6.725 15.768 ;
     RECT  6.401 14.688 6.761 14.712 ;
     RECT  5.404 30.96 6.761 30.984 ;
     RECT  5.645 47.712 6.761 47.736 ;
     RECT  6.005 8.064 7.808 8.808 ;
     RECT  5.717 10.656 7.808 10.68 ;
     RECT  5.645 17.616 7.808 18.456 ;
     RECT  6.545 22.464 7.808 22.488 ;
     RECT  5.404 28.464 7.808 28.488 ;
     RECT  6.257 38.448 7.808 39.816 ;
     RECT  5.933 43.392 7.808 43.416 ;
     RECT  5.404 45.456 7.808 45.48 ;
     RECT  7.808 2.148 7.912 54.012 ;
     RECT  7.912 2.418 8.104 53.742 ;
     RECT  8.104 28.464 10.508 28.488 ;
     RECT  10.508 2.148 10.612 54.012 ;
     RECT  10.612 2.148 10.748 53.742 ;
     RECT  10.748 1.728 10.804 53.742 ;
     RECT  10.804 1.728 10.835 1.752 ;
     RECT  12.005 21.648 12.037 21.672 ;
     RECT  12.037 6.864 12.044 6.888 ;
     RECT  12.044 11.232 12.085 11.256 ;
     RECT  12.044 12.864 12.085 12.888 ;
     RECT  12.044 26.688 12.085 26.712 ;
     RECT  12.013 5.664 12.097 5.688 ;
     RECT  12.037 18.192 12.124 18.216 ;
     RECT  12.037 19.536 12.124 19.56 ;
     RECT  12.037 20.832 12.124 21.672 ;
     RECT  12.044 6.864 12.125 7.272 ;
     RECT  12.125 7.248 12.131 7.272 ;
     RECT  12.044 8.496 12.131 8.52 ;
     RECT  12.044 9.936 12.131 9.96 ;
     RECT  12.085 11.232 12.131 12.888 ;
     RECT  12.044 13.92 12.131 13.944 ;
     RECT  12.044 23.664 12.131 23.688 ;
     RECT  12.044 25.056 12.131 25.08 ;
     RECT  12.085 26.688 12.131 27.384 ;
     RECT  12.044 29.616 12.131 29.64 ;
     RECT  12.044 31.008 12.131 31.032 ;
     RECT  12.044 40.752 12.131 40.776 ;
     RECT  12.044 41.856 12.131 41.88 ;
     RECT  12.044 43.488 12.131 43.512 ;
     RECT  12.044 44.88 12.131 44.904 ;
     RECT  12.044 46.176 12.131 46.2 ;
     RECT  12.044 47.616 12.131 47.64 ;
     RECT  12.044 48.864 12.131 48.888 ;
     RECT  12.044 50.304 12.131 50.328 ;
     RECT  12.049 15.408 12.133 15.432 ;
     RECT  12.049 32.496 12.133 32.52 ;
     RECT  12.131 27.36 12.169 27.384 ;
     RECT  12.085 51.312 12.169 51.336 ;
     RECT  12.124 21.648 12.373 21.672 ;
     RECT  12.337 35.28 12.517 35.304 ;
     RECT  12.085 36.48 12.517 36.504 ;
     RECT  12.131 12.192 13.208 12.312 ;
     RECT  12.373 21.648 13.208 21.96 ;
     RECT  10.804 28.464 13.208 28.488 ;
     RECT  12.517 35.28 13.208 36.504 ;
     RECT  13.208 2.148 13.312 54.012 ;
     RECT  13.312 2.418 13.504 53.742 ;
     RECT  13.504 11.184 13.667 12.552 ;
     RECT  13.504 21.936 13.667 22.44 ;
     RECT  13.504 29.616 13.715 29.64 ;
     RECT  13.504 32.304 13.715 32.328 ;
     RECT  13.504 33.6 13.715 33.624 ;
     RECT  13.504 34.8 13.717 36.456 ;
     RECT  13.504 31.008 13.756 31.032 ;
     RECT  13.504 8.16 13.763 8.184 ;
     RECT  13.504 9.456 13.763 9.48 ;
     RECT  13.667 11.184 13.763 11.208 ;
     RECT  13.504 18.048 13.763 18.072 ;
     RECT  13.504 19.536 13.763 19.56 ;
     RECT  13.504 20.784 13.763 20.808 ;
     RECT  13.667 22.08 13.763 22.44 ;
     RECT  13.504 23.664 13.763 23.688 ;
     RECT  13.504 25.056 13.763 25.08 ;
     RECT  13.504 26.352 13.763 26.376 ;
     RECT  13.504 27.36 13.763 27.384 ;
     RECT  13.717 35.28 13.763 36.456 ;
     RECT  13.504 37.584 13.763 37.608 ;
     RECT  13.504 47.28 13.763 47.304 ;
     RECT  13.504 49.008 13.763 49.032 ;
     RECT  13.504 50.448 13.763 51.336 ;
     RECT  13.504 6.816 13.789 6.84 ;
     RECT  13.504 38.784 13.789 38.808 ;
     RECT  13.763 51.312 13.789 51.336 ;
     RECT  13.667 12.432 13.811 12.552 ;
     RECT  13.504 13.92 13.811 14.856 ;
     RECT  13.504 43.296 13.811 43.32 ;
     RECT  13.504 44.784 13.852 44.904 ;
     RECT  13.763 22.176 13.925 22.44 ;
     RECT  13.763 35.28 13.961 35.496 ;
     RECT  14.497 23.904 14.753 23.928 ;
     RECT  13.925 22.176 15.26 22.2 ;
     RECT  15.26 22.176 15.281 23.16 ;
     RECT  13.504 28.464 15.289 28.488 ;
     RECT  15.26 46.896 15.289 46.92 ;
     RECT  13.811 12.528 15.301 12.552 ;
     RECT  13.961 35.472 15.301 35.496 ;
     RECT  13.852 44.88 15.308 44.904 ;
     RECT  15.289 28.464 15.397 29.064 ;
     RECT  15.301 34.32 15.397 34.344 ;
     RECT  15.301 35.472 15.397 35.88 ;
     RECT  15.301 31.584 15.865 31.608 ;
     RECT  15.281 6.24 15.908 6.264 ;
     RECT  15.26 7.632 15.908 7.656 ;
     RECT  15.301 8.928 15.908 8.952 ;
     RECT  15.301 10.56 15.908 10.584 ;
     RECT  15.301 11.616 15.908 13.272 ;
     RECT  15.26 14.64 15.908 14.664 ;
     RECT  15.289 15.984 15.908 16.008 ;
     RECT  15.325 18.768 15.908 18.792 ;
     RECT  15.325 19.968 15.908 19.992 ;
     RECT  15.281 21.792 15.908 23.16 ;
     RECT  15.26 24.48 15.908 24.504 ;
     RECT  15.281 25.68 15.908 25.704 ;
     RECT  15.397 28.368 15.908 29.064 ;
     RECT  15.26 30.336 15.908 30.36 ;
     RECT  15.865 31.584 15.908 31.944 ;
     RECT  15.301 33.216 15.908 33.24 ;
     RECT  15.397 34.32 15.908 35.88 ;
     RECT  15.301 37.008 15.908 37.032 ;
     RECT  15.281 38.208 15.908 38.232 ;
     RECT  15.301 40.176 15.908 40.2 ;
     RECT  15.26 41.472 15.908 41.496 ;
     RECT  15.281 42.768 15.908 42.792 ;
     RECT  15.308 44.88 15.908 45.576 ;
     RECT  15.289 46.752 15.908 46.92 ;
     RECT  15.26 48.432 15.908 48.456 ;
     RECT  15.281 49.584 15.908 49.608 ;
     RECT  15.908 2.148 16.012 54.012 ;
     RECT  16.012 2.418 16.204 53.742 ;
     RECT  16.204 31.488 16.373 31.944 ;
     RECT  16.204 38.496 16.373 38.664 ;
     RECT  16.204 34.32 16.625 35.88 ;
     RECT  16.204 43.92 16.625 45.576 ;
     RECT  16.204 6.288 16.931 6.312 ;
     RECT  16.204 7.728 16.931 7.752 ;
     RECT  16.204 8.976 16.931 9 ;
     RECT  16.204 10.416 16.931 10.44 ;
     RECT  16.204 11.664 16.931 11.688 ;
     RECT  16.204 20.112 16.931 20.136 ;
     RECT  16.204 21.36 16.931 22.92 ;
     RECT  16.204 24.48 16.931 24.504 ;
     RECT  16.373 31.488 16.931 31.512 ;
     RECT  16.204 33.072 16.931 33.096 ;
     RECT  16.625 34.32 16.931 34.344 ;
     RECT  16.204 37.056 16.931 37.08 ;
     RECT  16.373 38.496 16.931 38.52 ;
     RECT  16.204 41.184 16.931 41.208 ;
     RECT  16.204 42.432 16.931 42.456 ;
     RECT  16.625 45.552 16.931 45.576 ;
     RECT  16.204 46.8 16.931 46.824 ;
     RECT  16.204 48.24 16.931 48.264 ;
     RECT  16.204 49.488 16.931 49.512 ;
     RECT  16.204 5.088 16.957 5.112 ;
     RECT  16.204 14.784 16.957 14.808 ;
     RECT  16.204 15.984 16.957 16.008 ;
     RECT  16.204 18.768 16.957 18.792 ;
     RECT  16.931 22.176 16.957 22.2 ;
     RECT  16.204 25.68 16.957 25.704 ;
     RECT  16.204 30.192 16.957 30.216 ;
     RECT  16.625 35.856 16.957 35.88 ;
     RECT  16.204 39.888 16.957 39.912 ;
     RECT  16.625 43.92 16.957 43.944 ;
     RECT  16.204 50.736 16.957 50.76 ;
     RECT  17.593 24.72 18.608 24.744 ;
     RECT  16.204 28.464 18.608 28.488 ;
     RECT  18.608 2.148 18.712 54.012 ;
     RECT  18.712 2.418 18.904 53.742 ;
     RECT  18.904 24.72 18.965 26.04 ;
     RECT  18.904 28.08 18.965 29.496 ;
     RECT  18.965 28.08 19.897 28.104 ;
     RECT  18.904 5.232 19.933 5.256 ;
     RECT  18.904 6.624 19.933 6.648 ;
     RECT  18.904 8.688 19.933 8.712 ;
     RECT  18.904 15.984 19.933 16.008 ;
     RECT  18.904 19.104 19.933 19.128 ;
     RECT  18.904 20.112 19.933 20.616 ;
     RECT  18.904 21.936 19.933 21.96 ;
     RECT  18.904 23.232 19.933 23.256 ;
     RECT  18.965 25.68 19.933 26.04 ;
     RECT  19.897 27.744 19.933 28.104 ;
     RECT  18.965 29.136 19.933 29.496 ;
     RECT  18.904 36.048 19.933 38.184 ;
     RECT  18.904 45.072 19.933 45.768 ;
     RECT  18.904 47.856 19.933 48.216 ;
     RECT  18.904 49.584 19.933 49.608 ;
     RECT  18.904 50.592 19.933 50.616 ;
     RECT  19.933 4.512 19.969 9.384 ;
     RECT  19.933 10.416 19.969 14.616 ;
     RECT  19.933 15.6 19.969 16.68 ;
     RECT  19.933 17.712 19.969 34.008 ;
     RECT  19.933 35.04 19.969 41.64 ;
     RECT  19.933 42.624 19.969 42.648 ;
     RECT  19.933 43.68 19.969 44.04 ;
     RECT  19.933 45.072 19.969 51.672 ;
     RECT  19.969 4.512 21.42 51.672 ;
    LAYER M5 ;
     RECT  10.8 0.144 10.824 1.763 ;
     RECT  10.8 1.763 10.812 2.137 ;
     RECT  2.4 2.137 2.52 2.151 ;
     RECT  5.1 2.137 5.22 2.151 ;
     RECT  7.8 2.137 7.92 2.151 ;
     RECT  13.2 2.137 13.32 2.151 ;
     RECT  15.9 2.137 16.02 2.151 ;
     RECT  18.6 2.137 18.72 2.151 ;
     RECT  15.9 2.151 16.212 5.077 ;
     RECT  2.4 2.151 2.712 5.893 ;
     RECT  2.304 5.893 2.712 6.083 ;
     RECT  15.9 5.077 16.92 6.229 ;
     RECT  13.2 2.151 13.512 6.805 ;
     RECT  12.048 5.653 12.072 6.899 ;
     RECT  2.4 6.083 2.712 7.861 ;
     RECT  2.4 7.861 2.808 8.579 ;
     RECT  2.4 8.579 2.712 9.541 ;
     RECT  13.2 6.805 13.752 11.219 ;
     RECT  15.312 6.229 16.92 11.699 ;
     RECT  1.968 9.541 2.712 12.037 ;
     RECT  13.2 11.219 13.656 12.421 ;
     RECT  1.968 12.037 2.808 12.803 ;
     RECT  1.968 12.803 2.712 14.629 ;
     RECT  15.312 11.699 16.212 14.773 ;
     RECT  13.2 12.421 13.8 14.867 ;
     RECT  12.096 7.237 12.12 15.443 ;
     RECT  1.968 14.629 2.808 15.829 ;
     RECT  15.312 14.773 16.92 16.019 ;
     RECT  0.288 15.733 0.312 16.259 ;
     RECT  1.968 15.829 3.384 16.309 ;
     RECT  13.2 14.867 13.656 18.037 ;
     RECT  15.9 16.019 16.212 18.757 ;
     RECT  18.6 2.151 18.912 19.093 ;
     RECT  15.36 18.757 16.92 20.003 ;
     RECT  18.6 19.093 19.128 20.437 ;
     RECT  12.048 18.181 12.072 21.683 ;
     RECT  15.9 20.003 16.92 21.781 ;
     RECT  18.6 20.437 19.176 21.971 ;
     RECT  13.2 18.037 13.752 22.451 ;
     RECT  5.1 2.151 5.412 23.317 ;
     RECT  13.2 22.451 13.512 23.653 ;
     RECT  15.312 21.781 16.92 25.715 ;
     RECT  12.096 23.653 12.12 27.395 ;
     RECT  13.2 23.653 13.752 27.395 ;
     RECT  15.408 25.715 16.212 29.029 ;
     RECT  13.2 27.395 13.512 29.605 ;
     RECT  15.312 29.029 16.212 30.181 ;
     RECT  1.968 16.309 3.672 30.371 ;
     RECT  12.096 29.605 12.12 32.531 ;
     RECT  2.304 30.371 3.672 33.059 ;
     RECT  15.312 30.181 16.92 34.355 ;
     RECT  13.2 29.605 13.704 35.269 ;
     RECT  15.504 34.355 16.212 35.845 ;
     RECT  18.6 21.971 18.912 36.037 ;
     RECT  12.528 35.269 13.752 36.515 ;
     RECT  18.6 36.037 19.032 38.195 ;
     RECT  15.312 35.845 16.92 38.243 ;
     RECT  15.504 38.243 16.92 38.531 ;
     RECT  13.2 36.515 13.752 38.819 ;
     RECT  2.304 33.059 3.384 39.539 ;
     RECT  15.504 38.531 16.212 39.877 ;
     RECT  5.1 23.317 6.12 39.923 ;
     RECT  0.288 39.733 0.312 40.019 ;
     RECT  15.504 39.877 16.92 40.165 ;
     RECT  2.304 39.539 2.856 40.643 ;
     RECT  15.312 40.165 16.92 42.803 ;
     RECT  13.2 38.819 13.512 43.285 ;
     RECT  15.504 42.803 16.92 43.955 ;
     RECT  13.2 43.285 13.8 44.819 ;
     RECT  15.504 43.955 16.212 45.541 ;
     RECT  15.36 45.541 16.92 46.885 ;
     RECT  13.2 44.819 13.512 47.269 ;
     RECT  2.304 40.643 2.808 48.515 ;
     RECT  15.312 46.885 16.92 49.619 ;
     RECT  15.9 49.619 16.92 50.771 ;
     RECT  2.4 48.515 2.808 51.203 ;
     RECT  12.096 40.741 12.12 51.347 ;
     RECT  13.2 47.269 13.752 51.347 ;
     RECT  2.4 51.203 2.712 54.009 ;
     RECT  5.1 39.923 5.412 54.009 ;
     RECT  7.8 2.151 8.112 54.009 ;
     RECT  10.5 2.137 10.812 54.009 ;
     RECT  13.2 51.347 13.512 54.009 ;
     RECT  15.9 50.771 16.212 54.009 ;
     RECT  18.6 38.195 18.912 54.009 ;
     RECT  2.4 54.009 2.52 54.023 ;
     RECT  5.1 54.009 5.22 54.023 ;
     RECT  7.8 54.009 7.92 54.023 ;
     RECT  10.5 54.009 10.62 54.023 ;
     RECT  13.2 54.009 13.32 54.023 ;
     RECT  15.9 54.009 16.02 54.023 ;
     RECT  18.6 54.009 18.72 54.023 ;
  END
END hbfd_rly_136_EW_fc_f2
END LIBRARY
